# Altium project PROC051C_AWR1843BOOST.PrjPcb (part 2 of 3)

## Sheet PROC051D_QSPI_Flash_Reference.SchDoc: QSPI flash section
size 431 x 279 mm; Date: Not shown in title block; ApprovedBy: Not shown in title block; CheckedBy: Not shown in title block; Author: Not shown in title block; CompanyName: Not shown in title block; Engineer: Not shown in title block; Organization: Not shown in title block; Address1: Not shown in title block; Address2: Not shown in title block; Address3: Not shown in title block; Address4: Not shown in title block; DocumentNumber: 6; Revision: Use project parameter SCH_Rev; SheetNumber: 6; SheetTotal: 16; PageSetup: Record=PageOptions¦CenterHorizontal=True¦CenterVertical=True¦PrintScale=1.00¦XCorrection=1.00¦YCorrection=1.00¦PrintKind=0¦BorderSize=5000000¦LeftOffset=0¦BottomOffset=0¦Orientation=2¦PaperLength=1000¦PaperWidth=1000¦Scale=100¦PaperSource=15¦PrintQuality=600¦MediaType=1¦DitherType=10¦PaperKind=Letter¦PrintScaleMode=1

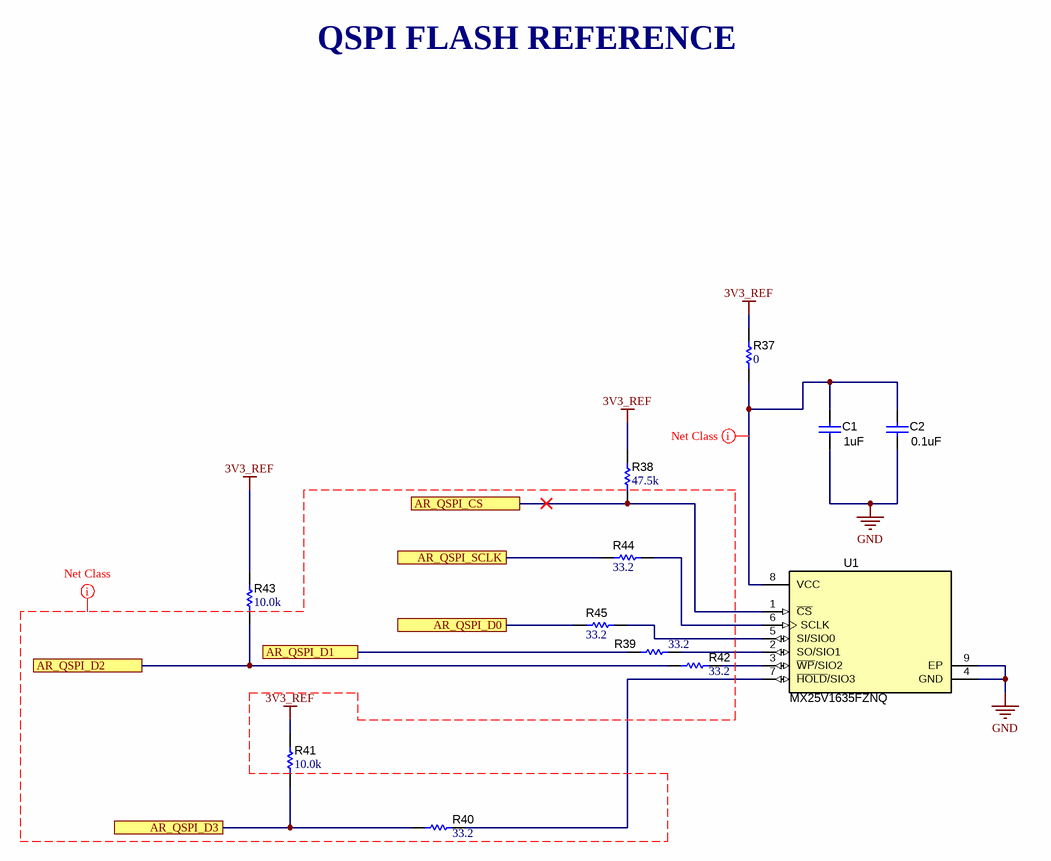
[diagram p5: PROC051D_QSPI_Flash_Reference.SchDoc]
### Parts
C1  ValueDisplayed: 1uF  [0603]  (hidden comment: GCM188R71C105KA64D)
C2  ValueDisplayed: 0.1uF  [0402L]  (hidden comment: CGA2B3X7R1H104K050BB)
R37  ValueDisplayed: 0  [0402L]  (hidden comment: ERJ-2GE0R00X)
R38  ValueDisplayed: 47.5k  [0402L]  (hidden comment: CRCW040247K5FKED)
R39  ValueDisplayed: 33.2  [0201_Silk]  (hidden comment: CRCW020133R2FNED)
R40  ValueDisplayed: 33.2  [0201_Silk]  (hidden comment: CRCW020133R2FNED)
R41  ValueDisplayed: 10.0k  [0402L]  (hidden comment: CRCW040210K0FKED)
R42  ValueDisplayed: 33.2  [0201_Silk]  (hidden comment: CRCW020133R2FNED)
R43  ValueDisplayed: 10.0k  [0402L]  (hidden comment: CRCW040210K0FKED)
R44  ValueDisplayed: 33.2  [0201_Silk]  (hidden comment: CRCW020133R2FNED)
R45  ValueDisplayed: 33.2  [0201_Silk]  (hidden comment: CRCW020133R2FNED)
U1  MX25V1635FZNQ  [WSON-8L_6x5MM_EP]

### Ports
AR_QSPI_CS, AR_QSPI_D0, AR_QSPI_D1, AR_QSPI_D2, AR_QSPI_D3, AR_QSPI_SCLK

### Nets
3V3_REF: R37.1 R38.2 R41.2 R43.2
GND: C1.1 C2.1 U1.4(GND) U1.9(EP)
AR_QSPI_CS: R38.1 U1.1(~{CS}) ; port AR_QSPI_CS
AR_QSPI_D0: R45.2 ; port AR_QSPI_D0
AR_QSPI_D1: R39.1 ; port AR_QSPI_D1
AR_QSPI_D2: R42.1 R43.1 ; port AR_QSPI_D2
AR_QSPI_D3: R40.2 R41.1 ; port AR_QSPI_D3
AR_QSPI_SCLK: R44.2 ; port AR_QSPI_SCLK
NetC1_2: C1.2 C2.2 R37.2 U1.8(VCC)
NetR39_2: R39.2 U1.2(SO/SIO1)
NetR40_1: R40.1 U1.7(~{HOLD}/SIO3)
NetR42_2: R42.2 U1.3(~{WP}/SIO2)
NetR44_1: R44.1 U1.6(SCLK)
NetR45_1: R45.1 U1.5(SI/SIO0)

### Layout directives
net class PWR: NetC1_2
net class QSPI: 3V3_REF

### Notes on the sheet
- QSPI FLASH REFERENCE

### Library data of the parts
C1 = CMP-0007136-5: CAP, CERM, 1 uF, 16 V, +/- 10%, X7R, AEC-Q200 Grade 1, 0603; Manufacturer: MuRata; TaMin_C: -55°C; Polarized: N; SizeAreaWB_mm2: 4.68; Value1: Unknown; U/M: EA; Value: 1uF; TaMax_C: 125°C; SizeZ_mm: 1; SizeX_mm: 1.6; SizeY_mm: 0.8; Value2: 16V; SizeArea_mm2: 1.28; AEC Qualified: Y; Cap_F: 1µF; AEC Category: Q200
C2 = CMP-0006325-2: CAP, CERM, 0.1 uF, 50 V, +/- 10%, X7R, AEC-Q200 Grade 1, 0402; Manufacturer: TDK; TaMin_C: -55°C; ESR_ohm: 0.039064; Polarized: N; SizeAreaWB_mm2: 3; Value1: 0.039064 ohm; U/M: EA; Value: 0.1uF; TaMax_C: 125°C; SizeZ_mm: 0.6; SizeX_mm: 1; SizeY_mm: 0.5; Cap_Case: 0402; Value2: 50V; AEC Qualified: Y; Cap_F: 100nF; IRMS_A: 8.14669dA; AEC Category: Q200
R37 = CMP-0026992-3: RES, 0, 5%, 0.1 W, AEC-Q200 Grade 0, 0402; Manufacturer: Panasonic; Power_W: 100mW; TempCo: 600 ppm/C; Value_Code: 0000; Value: 0; EIA_Code: E24; SizeX_mm: 1; SizeY_mm: 0.5; SizeZ_mm: 0.6; Value2: 0.1W; AEC Qualified: Y; VDC_V: 50V; AEC Category: Q200; SizeAreaWB_mm2: 3
R38 = CMP-0026395-2: RES, 47.5 k, 1%, 0.063 W, AEC-Q200 Grade 0, 0402; Manufacturer: Vishay-Dale; Power_W: 63mW; TempCo: 100 ppm/C; Value_Code: 47k5; Value: 47.5k; EIA_Code: E96; SizeX_mm: 1; SizeY_mm: 0.5; SizeZ_mm: 0.6; Value2: 0.063W; AEC Qualified: Y; VDC_V: 50V; AEC Category: Q200; AEC Grade: 0
R39 R40 R42 R45 = CMP-0027275-3: RES, 33.2, 1%, 0.05 W, 0201; Manufacturer: Vishay-Dale; Power_W: 50mW; TempCo: 200 ppm/C; Value_Code: 33R2; Value: 33.2; EIA_Code: E96; SizeX_mm: 0.6; SizeY_mm: 0.3; SizeZ_mm: 0.26; Value2: 0.05W; SizeArea_mm2: 0.18; AEC Qualified: N; AEC Category: Q200
R41 R43 = CMP-0025958-3: RES, 10.0 k, 1%, 0.063 W, AEC-Q200 Grade 0, 0402; Manufacturer: Vishay-Dale; Power_W: 63mW; TempCo: 100 ppm/C; Value_Code: 10k0; Value: 10.0k; EIA_Code: E96; Res_ohm: 10k; SizeX_mm: 1; SizeY_mm: 0.5; SizeZ_mm: 0.6; Value2: 0.063W; AEC Qualified: Y; VDC_V: 50V; AEC Category: Q200; AEC Grade: 0
R44 = CMP-0027275-3: RES, 33.2, 1%, 0.05 W, 0201; Manufacturer: Vishay-Dale; Power_W: 50mW; TempCo: 200 ppm/C; Value_Code: 33R2; Value: 33.2; EIA_Code: E96; SizeX_mm: 0.6; SizeY_mm: 0.3; SizeZ_mm: 0.26; Value2: 0.05W; SizeArea_mm2: 0.18; CompType: Resistor; AEC Qualified: N; AEC Category: Q200
U1 = CMP-0079267-1: 2.3V-3.6V, 16M-BIT [x 1/x 2/x 4] CMOS FLASH Memory, WSON-8; Manufacturer: Macronix International Co., LTD; SizeArea_mm2: 30; SizeAreaWB_mm2: 56; SizeY_mm: 5; SizeZ_mm: 0.8; SizeX_mm: 6

## Sheet PROC051D_SOP_Headers_Reference.SchDoc
size 431 x 279 mm; Date: Not shown in title block; ApprovedBy: Not shown in title block; CheckedBy: Not shown in title block; Author: Not shown in title block; CompanyName: Not shown in title block; Engineer: Not shown in title block; Organization: Not shown in title block; Address1: Not shown in title block; Address2: Not shown in title block; Address3: Not shown in title block; Address4: Not shown in title block; DocumentNumber: 7; Revision: Use project parameter SCH_Rev; SheetNumber: 7; SheetTotal: 16; PageSetup: Record=PageOptions¦CenterHorizontal=True¦CenterVertical=True¦PrintScale=1.00¦XCorrection=1.00¦YCorrection=1.00¦PrintKind=0¦BorderSize=5000000¦LeftOffset=0¦BottomOffset=0¦Orientation=2¦PaperLength=1000¦PaperWidth=1000¦Scale=100¦PaperSource=15¦PrintQuality=600¦MediaType=1¦DitherType=10¦PaperKind=Letter¦PrintScaleMode=1

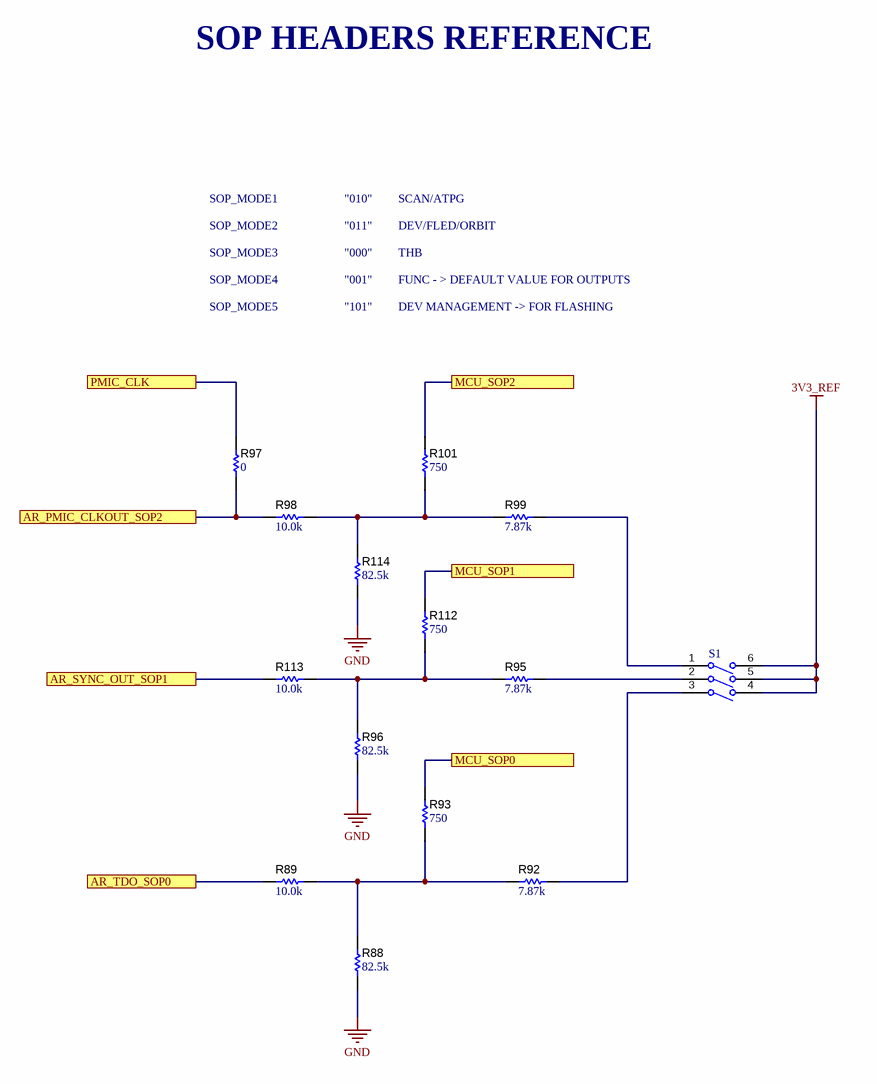
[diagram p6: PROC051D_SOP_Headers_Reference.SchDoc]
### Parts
R88  ValueDisplayed: 82.5k  [0402L]  (hidden comment: CRCW040282K5FKED)
R89  ValueDisplayed: 10.0k  [0402L]  (hidden comment: CRCW040210K0FKED)
R92  ValueDisplayed: 7.87k  [0402L]  (hidden comment: CRCW04027K87FKED)
R93  ValueDisplayed: 750  [0402L]  (hidden comment: CRCW0402750RFKED)
R95  ValueDisplayed: 7.87k  [0402L]  (hidden comment: CRCW04027K87FKED)
R96  ValueDisplayed: 82.5k  [0402L]  (hidden comment: CRCW040282K5FKED)
R97  ValueDisplayed: 0  [0402L]  (hidden comment: ERJ-2GE0R00X)
R98  ValueDisplayed: 10.0k  [0402L]  (hidden comment: CRCW040210K0FKED)
R99  ValueDisplayed: 7.87k  [0402L]  (hidden comment: CRCW04027K87FKED)
R101  ValueDisplayed: 750  [0402L]  (hidden comment: CRCW0402750RFKED)
R112  ValueDisplayed: 750  [0402L]  (hidden comment: CRCW0402750RFKED)
R113  ValueDisplayed: 10.0k  [0402L]  (hidden comment: CRCW040210K0FKED)
R114  ValueDisplayed: 82.5k  [0402L]  (hidden comment: CRCW040282K5FKED)
S1  219-3MST  [SW_219-3MST]  (value not drawn)

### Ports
AR_PMIC_CLKOUT_SOP2, AR_SYNC_OUT_SOP1, AR_TDO_SOP0, MCU_SOP0, MCU_SOP1, MCU_SOP2, PMIC_CLK

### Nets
3V3_REF: S1.4(B3) S1.5(B2) S1.6(B1)
GND: R88.1 R96.1 R114.1
AR_PMIC_CLKOUT_SOP2: R97.1 R98.1 ; port AR_PMIC_CLKOUT_SOP2
AR_SYNC_OUT_SOP1: R113.1 ; port AR_SYNC_OUT_SOP1
AR_TDO_SOP0: R89.1 ; port AR_TDO_SOP0
MCU_SOP0: R93.2 ; port MCU_SOP0
MCU_SOP1: R112.2 ; port MCU_SOP1
MCU_SOP2: R101.2 ; port MCU_SOP2
PMIC_CLK: R97.2 ; port PMIC_CLK
NetR88_2: R88.2 R89.2 R92.1 R93.1
NetR92_2: R92.2 S1.3(A3)
NetR95_1: R95.1 R96.2 R112.1 R113.2
NetR95_2: R95.2 S1.2(A2)
NetR98_2: R98.2 R99.1 R101.1 R114.2
NetR99_2: R99.2 S1.1(A1)

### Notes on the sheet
- SOP HEADERS REFERENCE
- SOP_MODE1
- "010"
- SCAN/ATPG
- SOP_MODE2
- SOP_MODE3
- "011"
- "000"
- DEV/FLED/ORBIT
- THB
- SOP_MODE4
- SOP_MODE5
- "001"
- "101"
- FUNC - > DEFAULT VALUE FOR OUTPUTS
- DEV MANAGEMENT -> FOR FLASHING

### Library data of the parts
R88 R96 R114 = CMP-0026574-2: RES, 82.5 k, 1%, 0.063 W, AEC-Q200 Grade 0, 0402; Manufacturer: Vishay-Dale; Power_W: 63mW; TempCo: 100 ppm/C; Value_Code: 82k5; Value: 82.5k; EIA_Code: E96; SizeX_mm: 1; SizeY_mm: 0.5; SizeZ_mm: 0.6; Value2: 0.063W; AEC Qualified: Y; VDC_V: 50V; AEC Grade: 0; AEC Category: Q200
R89 R98 R113 = CMP-0025958-3: as R41 on sheet PROC051D_QSPI_Flash_Reference
R92 R95 R99 = CMP-0026557-2: RES, 7.87 k, 1%, 0.063 W, AEC-Q200 Grade 0, 0402; Manufacturer: Vishay-Dale; Power_W: 63mW; TempCo: 100 ppm/C; Value_Code: 7k87; Value: 7.87k; EIA_Code: E96; SizeX_mm: 1; SizeY_mm: 0.5; SizeZ_mm: 0.6; Value2: 0.063W; AEC Qualified: Y; VDC_V: 50V; AEC Grade: 0; AEC Category: Q200
R93 R101 R112 = CMP-0026542-2: RES, 750, 1%, 0.063 W, AEC-Q200 Grade 0, 0402; Manufacturer: Vishay-Dale; Power_W: 63mW; TempCo: 100 ppm/C; Value_Code: 750R; Value: 750; EIA_Code: E96; SizeX_mm: 1; SizeY_mm: 0.5; SizeZ_mm: 0.6; Value2: 0.063W; AEC Qualified: Y; VDC_V: 50V; AEC Grade: 0; AEC Category: Q200
R97 = CMP-0026992-3: as R37 on sheet PROC051D_QSPI_Flash_Reference
S1 = CMP-0002269-1: Switch, SPST, Slide, Off-On, 3 Pos, 0.1A, 20V, SMD; Manufacturer: CTS Electrocomponents; CurrentRating_mA: 100A; PositionCount: 3

## Sheet PROC051D_RST_LEDs.SchDoc: Pwr_RST_LEDs
size 431 x 279 mm; Date: Not shown in title block; ApprovedBy: Not shown in title block; CheckedBy: Not shown in title block; Author: Not shown in title block; CompanyName: Not shown in title block; Engineer: Not shown in title block; Organization: Not shown in title block; Address1: Not shown in title block; Address2: Not shown in title block; Address3: Not shown in title block; Address4: Not shown in title block; DocumentNumber: 8; Revision: Use project parameter SCH_Rev; SheetNumber: 8; SheetTotal: 16; PageSetup: Record=PageOptions¦CenterHorizontal=True¦CenterVertical=True¦PrintScale=1.00¦XCorrection=1.00¦YCorrection=1.00¦PrintKind=0¦BorderSize=5000000¦LeftOffset=0¦BottomOffset=0¦Orientation=2¦PaperLength=1000¦PaperWidth=1000¦Scale=100¦PaperSource=15¦PrintQuality=600¦MediaType=1¦DitherType=10¦PaperKind=Letter¦PrintScaleMode=1

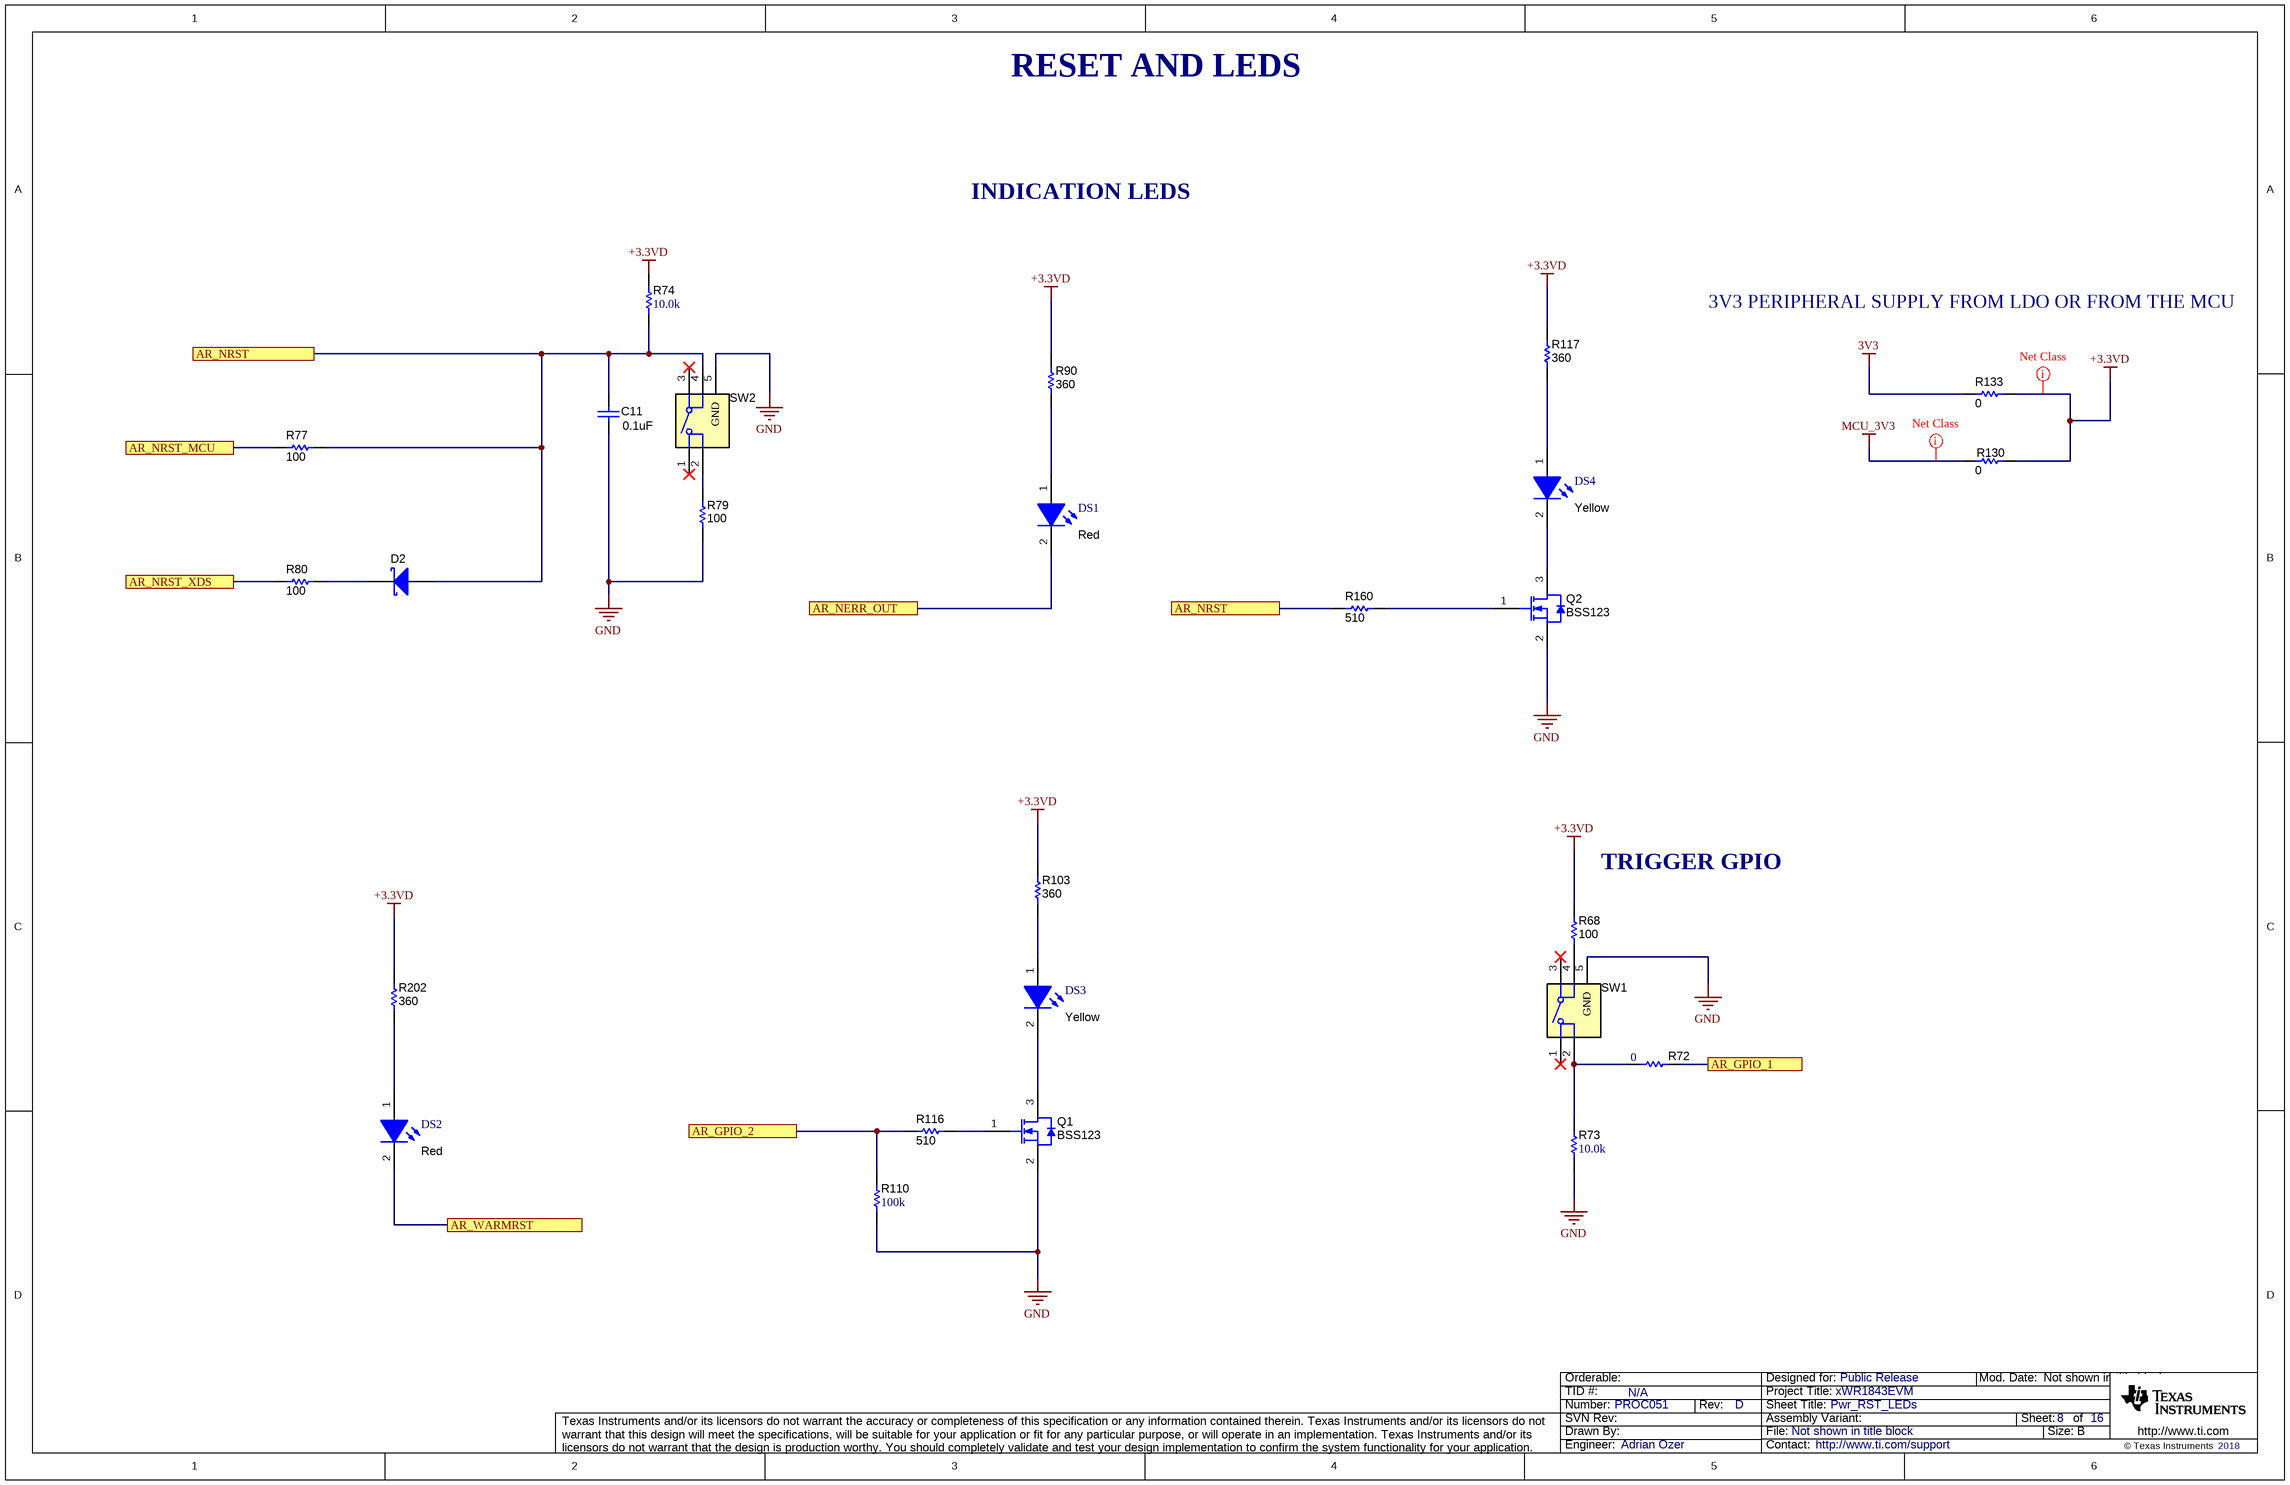
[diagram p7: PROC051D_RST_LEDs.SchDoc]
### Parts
C11  ValueDisplayed: 0.1uF  [0402L]  (hidden comment: GCM155R71C104KA55D)
D2  SMS3923-040LF  [SOD-882]  (value not drawn)
DS1  value Red  [LS L29K_Red]  (hidden comment: LS L29K-G1J2-1-Z)
DS2  value Red  [LS L29K_Red]  (hidden comment: LS L29K-G1J2-1-Z)
DS3  value Yellow  [SML-E1_Yellow]  (hidden comment: SML-E12Y8WT86)
DS4  value Yellow  [SML-E1_Yellow]  (hidden comment: SML-E12Y8WT86)
Q1  BSS123  [SOT-23]
Q2  BSS123  [SOT-23]
R68  ValueDisplayed: 100  [0402L]  (hidden comment: ERJ-2GEJ101X)
R72  ValueDisplayed: 0  [0201_Silk]  (hidden comment: CRCW02010000Z0ED)
R73  ValueDisplayed: 10.0k  [0402L]  (hidden comment: CRCW040210K0FKED)
R74  ValueDisplayed: 10.0k  [0402L]  (hidden comment: CRCW040210K0FKED)
R77  ValueDisplayed: 100  [0402L]  (hidden comment: ERJ-2GEJ101X)
R79  ValueDisplayed: 100  [0402L]  (hidden comment: ERJ-2GEJ101X)
R80  ValueDisplayed: 100  [0402L]  (hidden comment: ERJ-2GEJ101X)
R90  ValueDisplayed: 360  [0402L]  (hidden comment: ERJ-2GEJ361X)
R103  ValueDisplayed: 360  [0402L]  (hidden comment: ERJ-2GEJ361X)
R110  ValueDisplayed: 100k  [0402L]  (hidden comment: CRCW0402100KFKED)
R116  ValueDisplayed: 510  [0402L]  (hidden comment: ERJ-2GEJ511X)
R117  ValueDisplayed: 360  [0402L]  (hidden comment: ERJ-2GEJ361X)
R130  ValueDisplayed: 0  [0603]  (hidden comment: MCT06030Z0000ZP500)
R133  ValueDisplayed: 0  [0603]  (hidden comment: MCT06030Z0000ZP500)
R160  ValueDisplayed: 510  [0402L]  (hidden comment: ERJ-2GEJ511X)
R202  ValueDisplayed: 360  [0402L]  (hidden comment: ERJ-2GEJ361X)
SW1  KMR243GLFG  [SW_KMR243GLFG]  (value not drawn)
SW2  KMR243GLFG  [SW_KMR243GLFG]  (value not drawn)

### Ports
AR_GPIO_1, AR_GPIO_2, AR_NERR_OUT, AR_NRST, AR_NRST_MCU, AR_NRST_XDS, AR_WARMRST

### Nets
3V3: R133.1
+3.3VD: R68.2 R74.2 R90.2 R103.2 R117.2 R130.2 R133.2 R202.2
GND: C11.1 Q1.2(S) Q2.2(S) R73.1 R79.1 R110.1 SW1.5(GND) SW2.5(GND)
MCU_3V3: R130.1
AR_GPIO_1: R72.2 ; port AR_GPIO_1
AR_GPIO_2: R110.2 R116.1 ; port AR_GPIO_2
AR_NERR_OUT: DS1.2(K) ; port AR_NERR_OUT
AR_NRST: C11.2 D2.2(A) R74.1 R77.2 R160.1 SW2.4 ; port AR_NRST
AR_NRST_MCU: R77.1 ; port AR_NRST_MCU
AR_NRST_XDS: R80.1 ; port AR_NRST_XDS
AR_WARMRST: DS2.2(K) ; port AR_WARMRST
NetD2_1: D2.1(K) R80.2
NetDS1_1: DS1.1(A) R90.1
NetDS2_1: DS2.1(A) R202.1
NetDS3_1: DS3.1(A) R103.1
NetDS3_2: DS3.2(K) Q1.3(D)
NetDS4_1: DS4.1(A) R117.1
NetDS4_2: DS4.2(K) Q2.3(D)
NetQ1_1: Q1.1(G) R116.2
NetQ2_1: Q2.1(G) R160.2
NetR68_1: R68.1 SW1.4
NetR72_1: R72.1 R73.2 SW1.2
NetR79_2: R79.2 SW2.2

Not connected (* = marked no-connect by the designer): SW1 1* 3*; SW2 1* 3*

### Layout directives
net class PWR: +3.3VD, MCU_3V3

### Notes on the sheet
- RESET AND LEDS
- INDICATION LEDS
- 3V3 PERIPHERAL SUPPLY FROM LDO OR FROM THE MCU
- (near R68) TRIGGER GPIO

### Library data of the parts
C11 = CMP-0006351-2: CAP, CERM, 0.1 uF, 16 V, +/- 10%, X7R, 0402; Manufacturer: MuRata; TaMin_C: -55°C; Polarized: N; SizeAreaWB_mm2: 3; Value1: Unknown; U/M: EA; Value: 0.1uF; TaMax_C: 125°C; SizeZ_mm: 0.6; SizeX_mm: 1; SizeY_mm: 0.5; Cap_Case: 0402; Value2: 16V; Cap_F: 100nF; AEC Category: Q200
D2 = CMP-0078187-2: Diode, Schottky,  V, 0.01 A, SOD-882; Manufacturer: Skyworks Solutions; SizeAreaWB_mm2: 3.2; SizeArea_mm2: 0.6; AEC Qualified: N; TJmax_C: 150°C; AEC Category: Q101; SizeZ_mm: 0.5; Io_A: 10mA; Vf_V: 340mV; Value2: 0.34V; Value1: 0.01A; SizeX_mm: 1
DS1 DS2 = CMP-0002902-2: LED, Red, SMD; Manufacturer: OSRAM; Io_A: 20mA; Vr_V: 12V; Tjmax_C: 110°C; Value1: W; Angle: 160; Vf_V: 1.8V
DS3 DS4 = CMP-0002977-3: LED, Yellow, SMD; Manufacturer: Rohm; Io_A: 20mA; Power_TotalModule: 54mW; Vr_V: 5V; Tjmax_C: 85°C; Value1: 0.054W; Ir_A: 10µA; Vf_V: 2.2V; LuminousIntensity_IV: 63
Q1 Q2 = CMP-0000947-2: MOSFET, N-CH, 100 V, 0.17 A, SOT-23; Alternate Manufacturer: None; Manufacturer: Fairchild Semiconductor; SizeZ_mm: 1.1; ChType: N; Value2: 1.8 nC; Value1: 1; VdsMax_V: 100V; SizeX_mm: 2.5; SizeY_mm: 3; Vgs_V: 20V; Value: 100V; Rdson45_ohm: 10; SizeArea_mm2: 7.5; AEC Category: Q101; IdsMax_A: 1.7dA; SizeAreaWB_mm2: 14; U/M: EA; QgTyp_nC: 1.8
R68 R77 R79 R80 = CMP-0026993-2: RES, 100, 5%, 0.1 W, AEC-Q200 Grade 0, 0402; Manufacturer: Panasonic; Power_W: 100mW; TempCo: 200 ppm/C; Value_Code: 100R; U/M: EA; Value: 100; EIA_Code: E24; SizeX_mm: 1; SizeY_mm: 0.5; SizeZ_mm: 0.6; Value2: 0.1W; AEC Qualified: Y; AEC Grade: 0; AEC Category: Q200
R72 = CMP-0027008-4: RES, 0, 5%, 0.05 W, 0201; Manufacturer: Vishay-Dale; Power_W: 50mW; TempCo: ppm/C; Value_Code: 0000; Value: 0; EIA_Code: E24; SizeX_mm: 0.6; SizeY_mm: 0.3; SizeZ_mm: 0.26; Value2: 0.05W; SizeArea_mm2: 0.18; AEC Qualified: N; AEC Category: Q200
R73 R74 = CMP-0025958-3: as R41 on sheet PROC051D_QSPI_Flash_Reference
R90 R103 R117 R202 = CMP-0078194-1: RES, 360, 5%, 0.1 W, AEC-Q200 Grade 0, 0402; Manufacturer: Panasonic; Value_Code: 360R; SizeArea_mm2: 0.5; AEC Qualified: Y; AEC Category: Q200; Value: 360; SizeZ_mm: 0.6; EIA_Code: E24; TempCo: 200 ppm/C; AEC Grade: 0; Power_W: 100mW; VDC_V: 50V; Value2: 0.1W; U/M: EA; SizeX_mm: 1
R110 = CMP-0025950-3: RES, 100 k, 1%, 0.063 W, AEC-Q200 Grade 0, 0402; Manufacturer: Vishay-Dale; Power_W: 63mW; TempCo: 100 ppm/C; Value: 100k; EIA_Code: E96; SizeX_mm: 1; SizeY_mm: 0.5; SizeZ_mm: 0.6; Value2: 0.063W; AEC Qualified: Y; VDC_V: 50V; AEC Category: Q200; AEC Grade: 0
R116 R160 = CMP-0078212-1: RES, 510, 5%, 0.1 W, AEC-Q200 Grade 0, 0402; Manufacturer: Panasonic; Value_Code: 510R; SizeArea_mm2: 0.5; AEC Qualified: Y; AEC Category: Q200; Value: 510; SizeZ_mm: 0.6; EIA_Code: E24; TempCo: 200 ppm/C; AEC Grade: 0; Power_W: 100mW; VDC_V: 50V; Value2: 0.1W; U/M: EA; SizeX_mm: 1
R130 = CMP-0025884-3: RES, 0, 5%, 0.125 W, 0603; Manufacturer: Vishay/Beyschlag; Power_W: 125mW; TempCo: ppm/C; Value_Code: 0000; U/M: EA; Value: 0; EIA_Code: E24; SizeX_mm: 1.6; SizeY_mm: 0.8; SizeZ_mm: 1; Value2: 0.125W; SizeArea_mm2: 1.28; CompType: Resistor; AEC Qualified: N; AEC Category: Q200
R133 = CMP-0025884-3: RES, 0, 5%, 0.125 W, 0603; Manufacturer: Vishay/Beyschlag; Power_W: 125mW; TempCo: ppm/C; Value_Code: 0000; U/M: EA; Value: 0; EIA_Code: E24; SizeX_mm: 1.6; SizeY_mm: 0.8; SizeZ_mm: 1; Value2: 0.125W; SizeArea_mm2: 1.28; AEC Qualified: N; AEC Category: Q200
SW1 SW2 = CMP-0002325-1: Switch, SPST-NO, Off-Mom, 0.01 A, 32 VDC, SMD; Manufacturer: C&K Components; CurrentRating_mA: 10A; PositionCount: 1; SizeX_mm: 4.6; SizeY_mm: 2.8; SizeZ_mm: 1.9; SizeArea_mm2: 12.88; VDC_V: 32V; SizeAreaWB_mm2: 21.28

## Sheet PROC051D_VPP_Supply.SchDoc: VPP_Supply
size 431 x 279 mm; Date: Not shown in title block; ApprovedBy: Not shown in title block; CheckedBy: Not shown in title block; Author: Not shown in title block; CompanyName: Not shown in title block; Engineer: Not shown in title block; Organization: Not shown in title block; Address1: Not shown in title block; Address2: Not shown in title block; Address3: Not shown in title block; Address4: Not shown in title block; DocumentNumber: 9; Revision: Use project parameter SCH_Rev; SheetNumber: 9; SheetTotal: 16; PageSetup: Record=PageOptions¦CenterHorizontal=True¦CenterVertical=True¦PrintScale=1.00¦XCorrection=1.00¦YCorrection=1.00¦PrintKind=0¦BorderSize=5000000¦LeftOffset=0¦BottomOffset=0¦Orientation=2¦PaperLength=1000¦PaperWidth=1000¦Scale=100¦PaperSource=15¦PrintQuality=600¦MediaType=1¦DitherType=10¦PaperKind=Letter¦PrintScaleMode=1

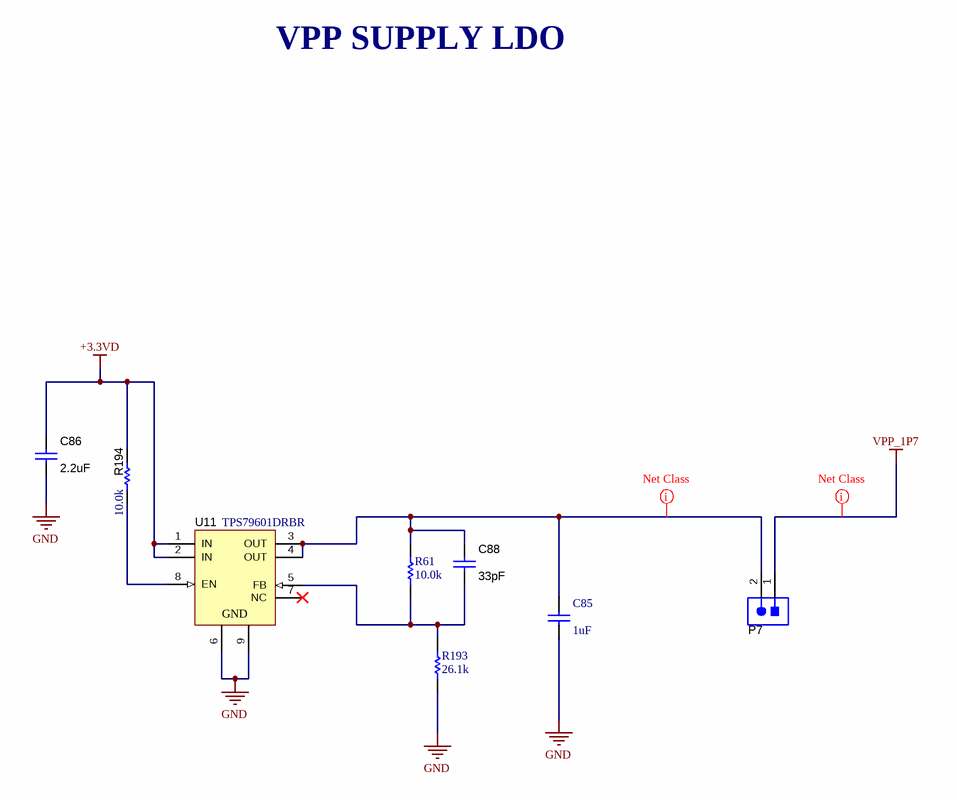
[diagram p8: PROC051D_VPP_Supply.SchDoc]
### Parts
C85  ValueDisplayed: 1uF  [0402]  (hidden comment: GRM155R70J105MA12D)
C86  ValueDisplayed: 2.2uF  [0402_065L]  (hidden comment: C1005X7S1A225K050BC)
C88  ValueDisplayed: 33pF  [0402L]  (hidden comment: C0402C330J5GAC)
P7  TSW-102-07-G-S  [TSW-102-07-G-S]  (value not drawn)
R61  ValueDisplayed: 10.0k  [0402]  (hidden comment: ERJ-2RKF1002X)
R193  ValueDisplayed: 26.1k  [0402]  (hidden comment: CRCW040226K1FKED)
R194  ValueDisplayed: 10.0k  [0402L]  (hidden comment: CRCW040210K0FKED)
U11  TPS79601DRBR  [DRB0008B]

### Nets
+3.3VD: C86.2 R194.1 U11.1(IN) U11.2(IN)
GND: C85.2 C86.1 R193.1 U11.6(GND) U11.9(GND)
VPP_1P7: P7.1
NetC85_1: C85.1 C88.1 P7.2 R61.2 U11.3(OUT) U11.4(OUT)
NetC88_2: C88.2 R61.1 R193.2 U11.5(FB)
NetR194_2: R194.2 U11.8(EN)

Not connected (* = marked no-connect by the designer): U11 7(NC)*

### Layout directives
net class PWR: NetC85_1, VPP_1P7

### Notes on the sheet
- VPP SUPPLY LDO

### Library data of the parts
C85 = CMP-0006624-2: CAP, CERM, 1 uF, 6.3 V, +/- 20%, X7R, 0402; Manufacturer: MuRata; TaMin_C: -55°C; Polarized: N; SizeAreaWB_mm2: 3; Value1: Unknown; U/M: EA; Value: 1uF; TaMax_C: 125°C; SizeZ_mm: 0.6; SizeX_mm: 1; SizeY_mm: 0.5; Value2: 6.3V; Cap_F: 1µF; AEC Category: Q200
C86 = CMP-0006302-2: CAP, CERM, 2.2 uF, 10 V, +/- 10%, X7S, 0402; Manufacturer: TDK; TaMin_C: -55°C; ESR_ohm: 5.925m; Polarized: N; SizeAreaWB_mm2: 3; Value1: 0.005925 ohm; U/M: EA; Value: 2.2uF; TaMax_C: 125°C; SizeZ_mm: 0.65; SizeX_mm: 1; SizeY_mm: 0.5; Cap_Case: 0402_065; Value2: 10V; CompType: Capacitor; Cap_F: 2.2µF; IRMS_A: 2.05591A; AEC Category: Q200
C88 = CMP-0006242-2: CAP, CERM, 33 pF, 50 V, +/- 5%, C0G/NP0, 0402; Manufacturer: Kemet; TaMin_C: -55°C; Polarized: N; SizeAreaWB_mm2: 3; Value1: Unknown; U/M: EA; Value: 33pF; TaMax_C: 125°C; SizeZ_mm: 0.6; SizeX_mm: 1; SizeY_mm: 0.5; Cap_Case: 0402; Value2: 50V; AEC Category: Q200
P7 = CMP-0075405-2: Header, 100mil, 2x1, Gold, TH; Manufacturer: Samtec; Pitch_mm: 2.54; Cert_VDE: N; Gender: Male; Cert_CSA: Y; Voltage_V: 550V; Green_REACh: Passed; Current_A: 6.3A; Green_Lifecycle: Active; Row_Count: 1
R61 = CMP-0026658-1: RES, 10.0 k, 1%, 0.1 W, 0402; Manufacturer: Panasonic; Power_W: 100mW; TempCo: 100 ppm/C; Value_Code: 10k0; U/M: EA; Value: 10.0k; EIA_Code: E96; Res_ohm: 10k; SizeX_mm: 1; SizeY_mm: 0.5; SizeZ_mm: 0.6; Value2: 0.1W; VDC_V: 50V; AEC Category: Q200
R193 = CMP-0026207-2: RES, 26.1 k, 1%, 0.063 W, AEC-Q200 Grade 0, 0402; Manufacturer: Vishay-Dale; Power_W: 63mW; TempCo: 100 ppm/C; Value_Code: 26k1; Value: 26.1k; EIA_Code: E96; SizeX_mm: 1; SizeY_mm: 0.5; SizeZ_mm: 0.6; Value2: 0.063W; AEC Qualified: Y; VDC_V: 50V; AEC Category: Q200; AEC Grade: 0
R194 = CMP-0025958-3: as R41 on sheet PROC051D_QSPI_Flash_Reference
U11 = CMP-0036402-3: Single Output High PSRR LDO, 1 A, Adjustable 1.2 to 5.5 V Output, 2.7 to 5.5 V Input, 8-pin SON (DRB), -40 to 125 degC, Green (RoHS & no Sb/Br); Manufacturer: Texas Instruments; Vin(Min)(V): 2.7; Vout Adj(Max)(V): 5.5; Vout Adj(Min)(V): 1.2; Accuracy(%): 2; SubFamily: Single Channel LDO; Iq(Typ)(mA): 0.26; Vdo(Typ)(mV): 250; Iout(Max)(A): 1; AEC Category: Q200; AEC Qualified: N; CompType: IC; SizeArea_mm2: 9.0; SizeAreaWB_mm2: 16.0; SizeX_mm: 3.0; SizeZ_mm: 1.0

## Sheet PROC051D_HD Connector.SchDoc: HD Connector
size 431 x 279 mm; Date: Not shown in title block; ApprovedBy: Not shown in title block; CheckedBy: Not shown in title block; Author: Not shown in title block; CompanyName: Not shown in title block; Engineer: Not shown in title block; Organization: Not shown in title block; Address1: Not shown in title block; Address2: Not shown in title block; Address3: Not shown in title block; Address4: Not shown in title block; DocumentNumber: 10; Revision: Use project parameter SCH_Rev; SheetNumber: 10; SheetTotal: 16; PageSetup: Record=PageOptions¦CenterHorizontal=True¦CenterVertical=True¦PrintScale=1.00¦XCorrection=1.00¦YCorrection=1.00¦PrintKind=0¦BorderSize=5000000¦LeftOffset=0¦BottomOffset=0¦Orientation=2¦PaperLength=1000¦PaperWidth=1000¦Scale=100¦PaperSource=15¦PrintQuality=600¦MediaType=1¦DitherType=10¦PrintScaleMode=1¦PaperKind=Letter

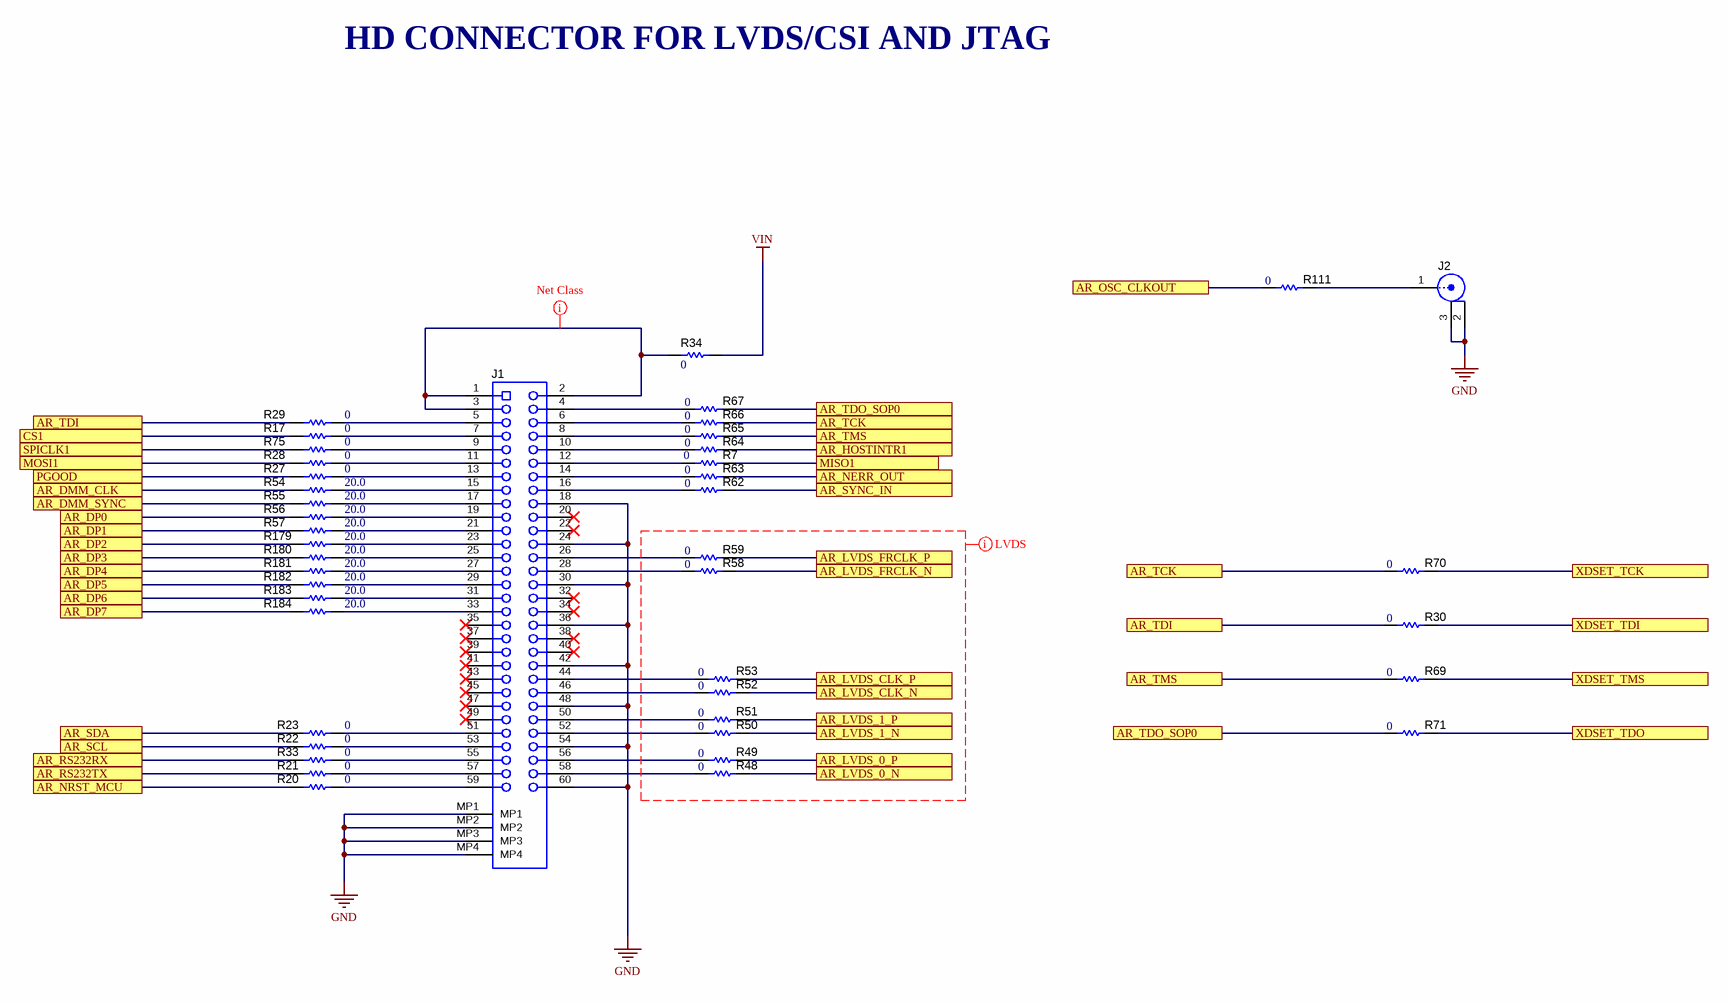
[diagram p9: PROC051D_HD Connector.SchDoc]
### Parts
J1  QSH-030-01-L-D-A  [Samtec_QSH-030-01-X-D-A]  (value not drawn)
J2  128-0711-201  [Johnson_128-0711-201]  (value not drawn)
R7  ValueDisplayed: 0  [0201_Silk]  (hidden comment: CRCW02010000Z0ED)
R17  ValueDisplayed: 0  [0201_Silk]  (hidden comment: CRCW02010000Z0ED)
R20  ValueDisplayed: 0  [0201_Silk]  (hidden comment: CRCW02010000Z0ED)
R21  ValueDisplayed: 0  [0201_Silk]  (hidden comment: CRCW02010000Z0ED)
R22  ValueDisplayed: 0  [0201_Silk]  (hidden comment: CRCW02010000Z0ED)
R23  ValueDisplayed: 0  [0201_Silk]  (hidden comment: CRCW02010000Z0ED)
R27  ValueDisplayed: 0  [0201_Silk]  (hidden comment: CRCW02010000Z0ED)
R28  ValueDisplayed: 0  [0201_Silk]  (hidden comment: CRCW02010000Z0ED)
R29  ValueDisplayed: 0  [0201_Silk]  (hidden comment: CRCW02010000Z0ED)
R30  ValueDisplayed: 0  [0201_Silk]  (hidden comment: CRCW02010000Z0ED)
R33  ValueDisplayed: 0  [0201_Silk]  (hidden comment: CRCW02010000Z0ED)
R34  ValueDisplayed: 0  [2010]  (hidden comment: CRCW20100000Z0EF)
R48  ValueDisplayed: 0  [0201_Silk]  (hidden comment: CRCW02010000Z0ED)
R49  ValueDisplayed: 0  [0201_Silk]  (hidden comment: CRCW02010000Z0ED)
R50  ValueDisplayed: 0  [0201_Silk]  (hidden comment: CRCW02010000Z0ED)
R51  ValueDisplayed: 0  [0201_Silk]  (hidden comment: CRCW02010000Z0ED)
R52  ValueDisplayed: 0  [0201_Silk]  (hidden comment: CRCW02010000Z0ED)
R53  ValueDisplayed: 0  [0201_Silk]  (hidden comment: CRCW02010000Z0ED)
R54  ValueDisplayed: 20.0  [0201_033]  (hidden comment: CRCW020120R0FNED)
R55  ValueDisplayed: 20.0  [0201_033]  (hidden comment: CRCW020120R0FNED)
R56  ValueDisplayed: 20.0  [0201_033]  (hidden comment: CRCW020120R0FNED)
R57  ValueDisplayed: 20.0  [0201_033]  (hidden comment: CRCW020120R0FNED)
R58  ValueDisplayed: 0  [0201_Silk]  (hidden comment: CRCW02010000Z0ED)
R59  ValueDisplayed: 0  [0201_Silk]  (hidden comment: CRCW02010000Z0ED)
R62  ValueDisplayed: 0  [0201_Silk]  (hidden comment: CRCW02010000Z0ED)
R63  ValueDisplayed: 0  [0201_Silk]  (hidden comment: CRCW02010000Z0ED)
R64  ValueDisplayed: 0  [0201_Silk]  (hidden comment: CRCW02010000Z0ED)
R65  ValueDisplayed: 0  [0201_Silk]  (hidden comment: CRCW02010000Z0ED)
R66  ValueDisplayed: 0  [0201_Silk]  (hidden comment: CRCW02010000Z0ED)
R67  ValueDisplayed: 0  [0201_Silk]  (hidden comment: CRCW02010000Z0ED)
R69  ValueDisplayed: 0  [0201_Silk]  (hidden comment: CRCW02010000Z0ED)
R70  ValueDisplayed: 0  [0201_Silk]  (hidden comment: CRCW02010000Z0ED)
R71  ValueDisplayed: 0  [0201_Silk]  (hidden comment: CRCW02010000Z0ED)
R75  ValueDisplayed: 0  [0201_Silk]  (hidden comment: CRCW02010000Z0ED)
R111  ValueDisplayed: 0  [0201_Silk]  (hidden comment: CRCW02010000Z0ED)
R179  ValueDisplayed: 20.0  [0201_033]  (hidden comment: CRCW020120R0FNED)
R180  ValueDisplayed: 20.0  [0201_033]  (hidden comment: CRCW020120R0FNED)
R181  ValueDisplayed: 20.0  [0201_033]  (hidden comment: CRCW020120R0FNED)
R182  ValueDisplayed: 20.0  [0201_033]  (hidden comment: CRCW020120R0FNED)
R183  ValueDisplayed: 20.0  [0201_033]  (hidden comment: CRCW020120R0FNED)
R184  ValueDisplayed: 20.0  [0201_033]  (hidden comment: CRCW020120R0FNED)

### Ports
AR_DMM_CLK, AR_DMM_SYNC, AR_DP0, AR_DP1, AR_DP2, AR_DP3, AR_DP4, AR_DP5, AR_DP6, AR_DP7, AR_HOSTINTR1, AR_LVDS_0_N, AR_LVDS_0_P, AR_LVDS_1_N, AR_LVDS_1_P, AR_LVDS_CLK_N, AR_LVDS_CLK_P, AR_LVDS_FRCLK_N, AR_LVDS_FRCLK_P, AR_NERR_OUT, AR_NRST_MCU, AR_OSC_CLKOUT, AR_RS232RX, AR_RS232TX, AR_SCL, AR_SDA, AR_SYNC_IN, AR_TCK, AR_TDI, AR_TDO_SOP0, AR_TMS, CS1, MISO1, MOSI1, PGOOD, SPICLK1, XDSET_TCK, XDSET_TDI, XDSET_TDO, XDSET_TMS

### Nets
GND: J1.18 J1.24 J1.30 J1.36 J1.42 J1.48 J1.54 J1.60 J1.MP1 J1.MP2 J1.MP3 J1.MP4 J2.2 J2.3
VIN: R34.2
AR_DMM_CLK: R54.1 ; port AR_DMM_CLK
AR_DMM_SYNC: R55.1 ; port AR_DMM_SYNC
AR_DP0: R56.1 ; port AR_DP0
AR_DP1: R57.1 ; port AR_DP1
AR_DP2: R179.1 ; port AR_DP2
AR_DP3: R180.1 ; port AR_DP3
AR_DP4: R181.1 ; port AR_DP4
AR_DP5: R182.1 ; port AR_DP5
AR_DP6: R183.1 ; port AR_DP6
AR_DP7: R184.1 ; port AR_DP7
AR_HOSTINTR1: R64.2 ; port AR_HOSTINTR1
AR_LVDS_0_N: R48.2 ; port AR_LVDS_0_N
AR_LVDS_0_P: R49.2 ; port AR_LVDS_0_P
AR_LVDS_1_N: R50.2 ; port AR_LVDS_1_N
AR_LVDS_1_P: R51.2 ; port AR_LVDS_1_P
AR_LVDS_CLK_N: R52.2 ; port AR_LVDS_CLK_N
AR_LVDS_CLK_P: R53.2 ; port AR_LVDS_CLK_P
AR_LVDS_FRCLK_N: R58.2 ; port AR_LVDS_FRCLK_N
AR_LVDS_FRCLK_P: R59.2 ; port AR_LVDS_FRCLK_P
AR_NERR_OUT: R63.2 ; port AR_NERR_OUT
AR_NRST_MCU: R20.1 ; port AR_NRST_MCU
AR_OSC_CLKOUT: R111.1 ; port AR_OSC_CLKOUT
AR_RS232RX: R33.1 ; port AR_RS232RX
AR_RS232TX: R21.1 ; port AR_RS232TX
AR_SCL: R22.1 ; port AR_SCL
AR_SDA: R23.1 ; port AR_SDA
AR_SYNC_IN: R62.2 ; port AR_SYNC_IN
AR_TCK: R66.2 R70.1 ; port AR_TCK
AR_TDI: R29.1 R30.1 ; port AR_TDI
AR_TDO_SOP0: R67.2 R71.1 ; port AR_TDO_SOP0
AR_TMS: R65.2 R69.1 ; port AR_TMS
CS1: R17.1 ; port CS1
MISO1: R7.2 ; port MISO1
MOSI1: R28.1 ; port MOSI1
PGOOD: R27.1 ; port PGOOD
SPICLK1: R75.1 ; port SPICLK1
XDSET_TCK: R70.2 ; port XDSET_TCK
XDSET_TDI: R30.2 ; port XDSET_TDI
XDSET_TDO: R71.2 ; port XDSET_TDO
XDSET_TMS: R69.2 ; port XDSET_TMS
NetJ1_1: J1.1 J1.2 J1.3 R34.1
NetJ1_4: J1.4 R67.1
NetJ1_5: J1.5 R29.2
NetJ1_6: J1.6 R66.1
NetJ1_7: J1.7 R17.2
NetJ1_8: J1.8 R65.1
NetJ1_9: J1.9 R75.2
NetJ1_10: J1.10 R64.1
NetJ1_11: J1.11 R28.2
NetJ1_12: J1.12 R7.1
NetJ1_13: J1.13 R27.2
NetJ1_14: J1.14 R63.1
NetJ1_15: J1.15 R54.2
NetJ1_16: J1.16 R62.1
NetJ1_17: J1.17 R55.2
NetJ1_19: J1.19 R56.2
NetJ1_21: J1.21 R57.2
NetJ1_23: J1.23 R179.2
NetJ1_25: J1.25 R180.2
NetJ1_26: J1.26 R59.1
NetJ1_27: J1.27 R181.2
NetJ1_28: J1.28 R58.1
NetJ1_29: J1.29 R182.2
NetJ1_31: J1.31 R183.2
NetJ1_33: J1.33 R184.2
NetJ1_44: J1.44 R53.1
NetJ1_46: J1.46 R52.1
NetJ1_50: J1.50 R51.1
NetJ1_51: J1.51 R23.2
NetJ1_52: J1.52 R50.1
NetJ1_53: J1.53 R22.2
NetJ1_55: J1.55 R33.2
NetJ1_56: J1.56 R49.1
NetJ1_57: J1.57 R21.2
NetJ1_58: J1.58 R48.1
NetJ1_59: J1.59 R20.2
NetJ2_1: J2.1 R111.2

Not connected (* = marked no-connect by the designer): J1 20* 22* 32* 34* 35* 37* 38* 39* 40* 41* 43* 45* 47* 49*

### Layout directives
net class Undefined: (no net found under the mark)
net class PWR: NetJ1_1

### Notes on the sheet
- HD CONNECTOR FOR LVDS/CSI AND JTAG

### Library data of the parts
J1 = CMP-0075524-1: Receptacle, 0.5 mm, 30x2, Gold, TH; Manufacturer: Samtec; Pitch_mm: 0.5; Gender: Female; Green_REACh: Passed; CT: False; Shrouded: N; RowSpacing_mm: 5.73; Green_Lifecycle: Active; Row_Count: 2
J2 = CMP-0055788-1: UMC Straight Jack Receptacle, 50 Ohm, Gold, SMT; Manufacturer: Cinch Connectivity; CNHeader: FALSE; Gender: Female
R7 R17 R20-R23 R27-R30 R33 R48-R53 R58 R59 R62-R67 R69-R71 R75 R111 = CMP-0027008-4: as R72 on sheet PROC051D_RST_LEDs
R34 = CMP-0016044-3: RES, 0, 5%, 0.75 W, AEC-Q200 Grade 0, 2010; Manufacturer: Vishay-Dale; Power_W: 750mW; TempCo: ppm/C; Value_Code: 0000; Value: 0; EIA_Code: E24; SizeX_mm: 5; SizeY_mm: 2.5; SizeZ_mm: 1.66; Value2: 0.75W; SizeArea_mm2: 12.5; AEC Qualified: Y; AEC Category: Q200
R54-R57 R179-R184 = CMP-0078192-2: RES, 20.0, 1%, 0.05 W, 0201; Manufacturer: Vishay-Dale; Value_Code: 20R0; SizeArea_mm2: 0.18; AEC Qualified: N; AEC Category: Q200; Res_ohm: 20; Value: 20.0; SizeZ_mm: 0.33; EIA_Code: E96; TempCo: 200 ppm/C; Power_W: 50mW; VDC_V: 30V; SizeY_mm: 0.3; Value2: 0.05W; SizeX_mm: 0.6

## Sheet PROC051D_LP Connector.SchDoc: LP Connector
size 431 x 279 mm; Date: Not shown in title block; ApprovedBy: Not shown in title block; CheckedBy: Not shown in title block; Author: Not shown in title block; CompanyName: Not shown in title block; Engineer: Not shown in title block; Organization: Not shown in title block; Address1: Not shown in title block; Address2: Not shown in title block; Address3: Not shown in title block; Address4: Not shown in title block; DocumentNumber: 11; Revision: Use project parameter SCH_Rev; SheetNumber: 11; SheetTotal: 16; PageSetup: Record=PageOptions¦CenterHorizontal=True¦CenterVertical=True¦PrintScale=1.00¦XCorrection=1.00¦YCorrection=1.00¦PrintKind=0¦BorderSize=5000000¦LeftOffset=0¦BottomOffset=0¦Orientation=2¦PaperLength=1000¦PaperWidth=1000¦Scale=100¦PaperSource=15¦PrintQuality=600¦MediaType=1¦DitherType=10¦PaperKind=Letter¦PrintScaleMode=1

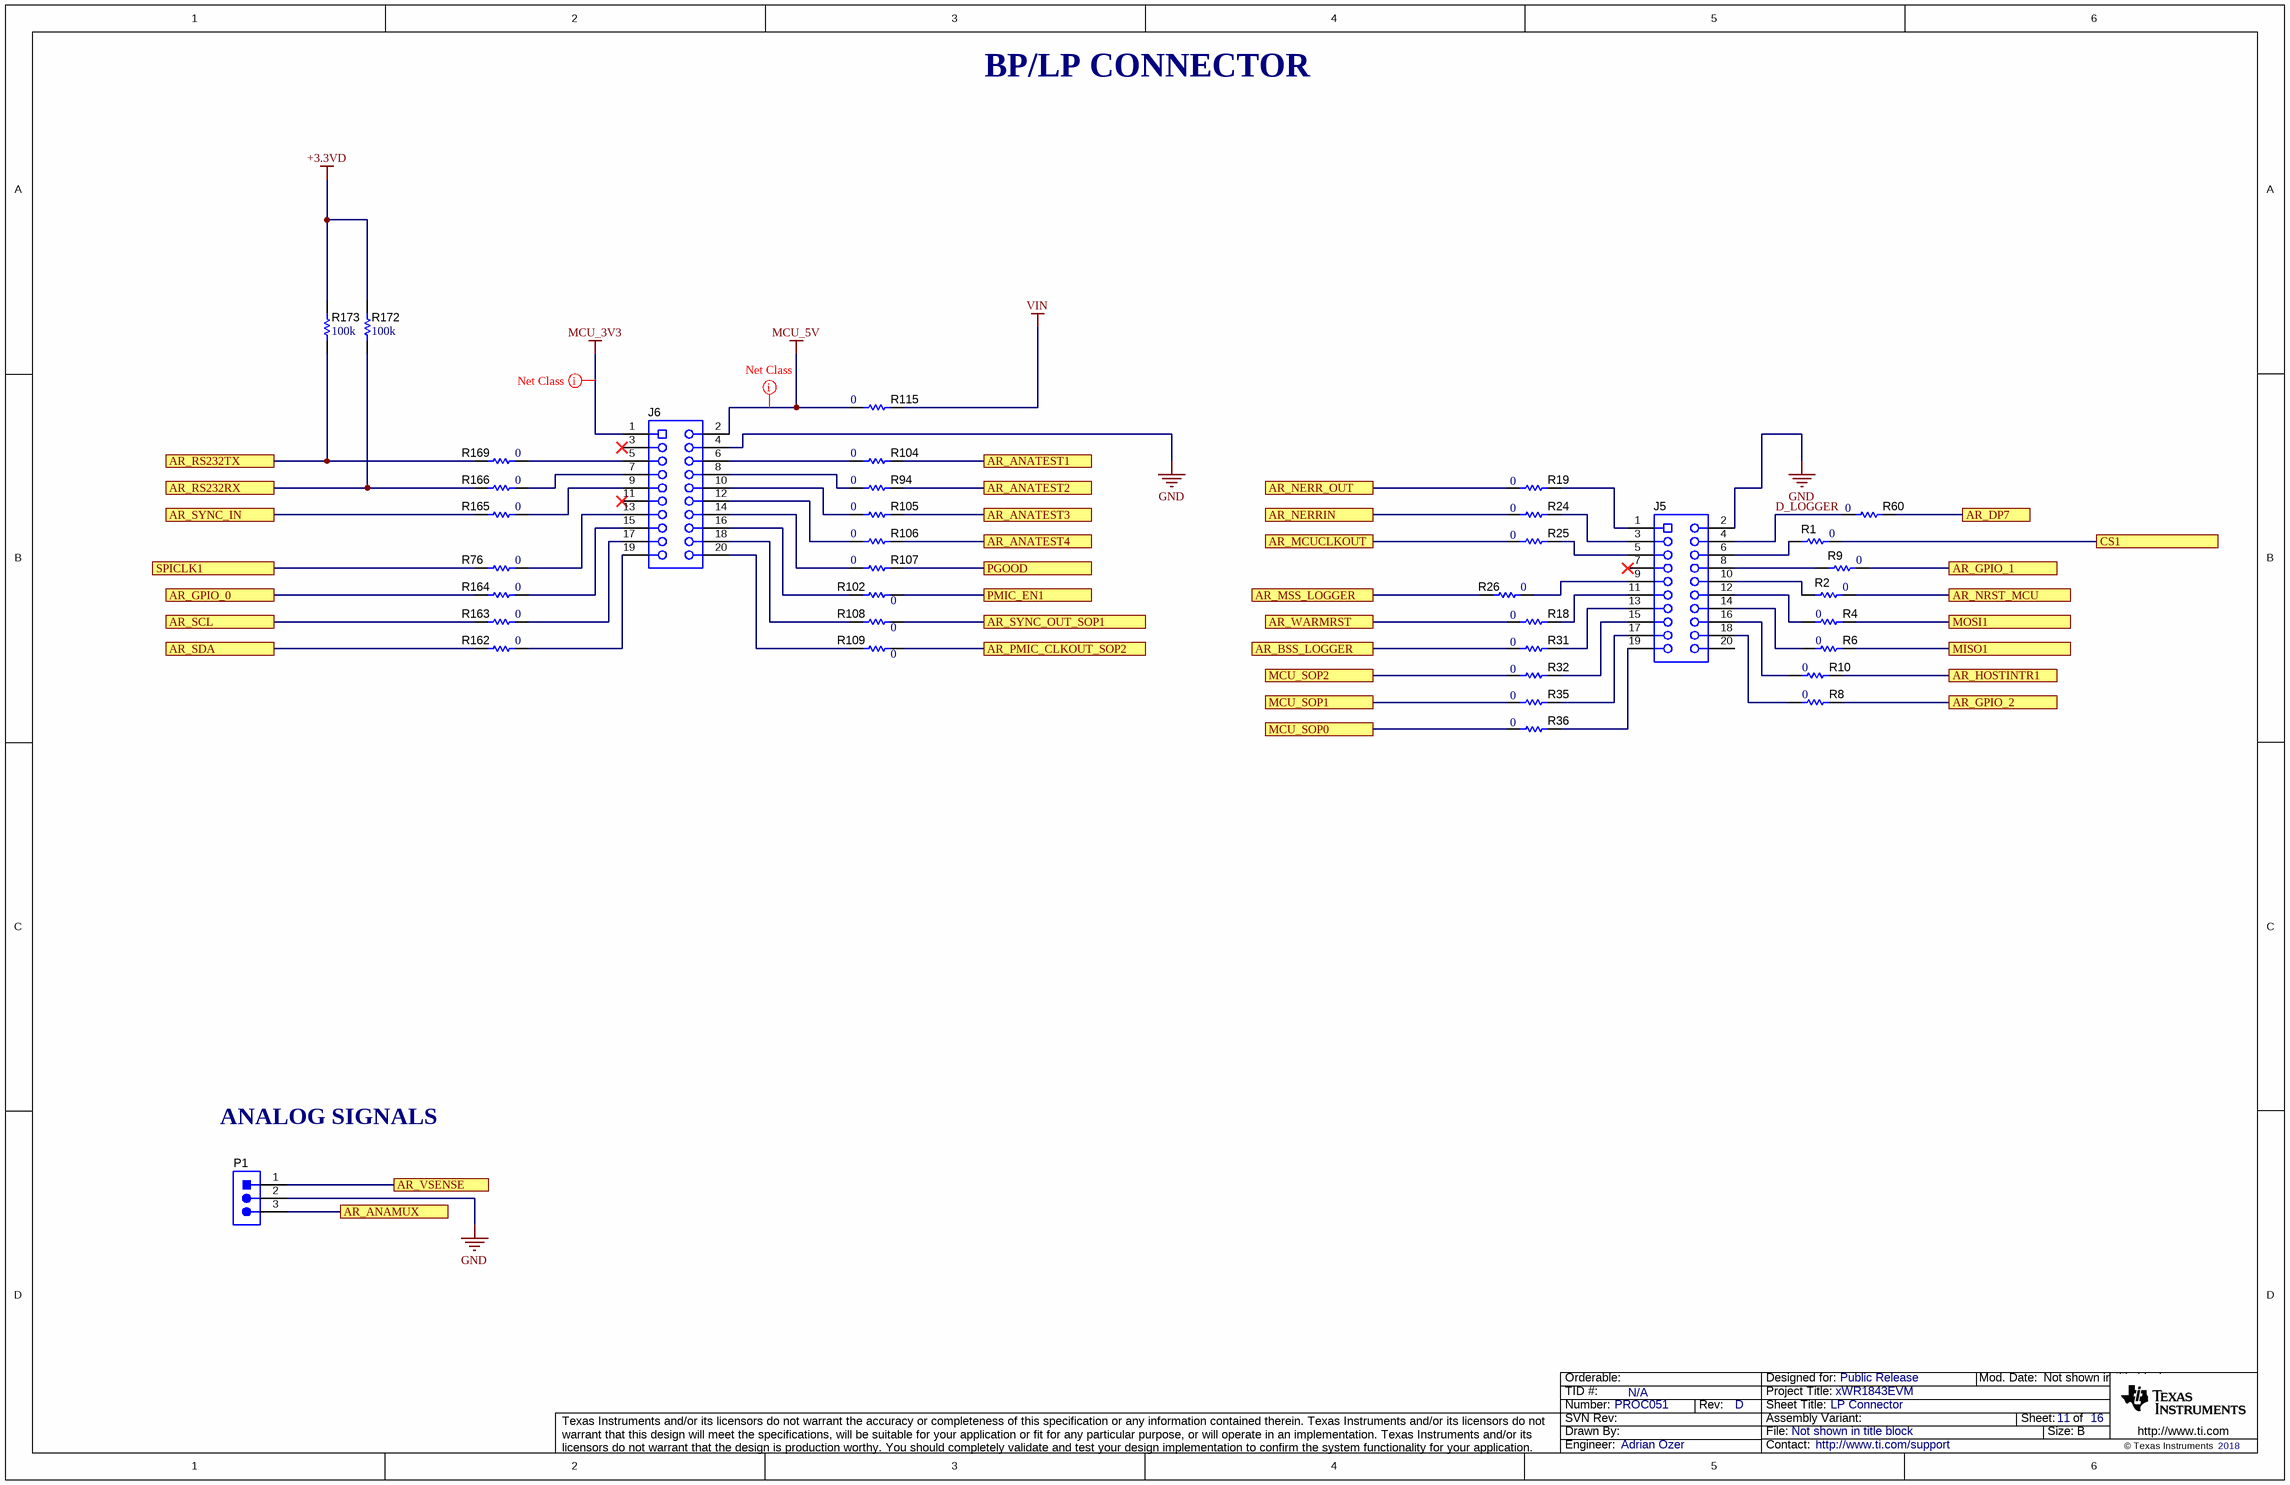
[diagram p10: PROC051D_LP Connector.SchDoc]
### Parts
J5  SSM-110-S-DV  [Samtec_SSM-110-x-DV]  (value not drawn)
J6  SSM-110-S-DV  [Samtec_SSM-110-x-DV]  (value not drawn)
P1  TSW-103-07-T-S  [Samtec_TSW-103-07-T-S]  (value not drawn)
R1  ValueDisplayed: 0  [0201_Silk]  (hidden comment: CRCW02010000Z0ED)
R2  ValueDisplayed: 0  [0201_Silk]  (hidden comment: CRCW02010000Z0ED)
R4  ValueDisplayed: 0  [0201_Silk]  (hidden comment: CRCW02010000Z0ED)
R6  ValueDisplayed: 0  [0201_Silk]  (hidden comment: CRCW02010000Z0ED)
R8  ValueDisplayed: 0  [0201_Silk]  (hidden comment: CRCW02010000Z0ED)
R9  ValueDisplayed: 0  [0201_Silk]  (hidden comment: CRCW02010000Z0ED)
R10  ValueDisplayed: 0  [0201_Silk]  (hidden comment: CRCW02010000Z0ED)
R18  ValueDisplayed: 0  [0201_Silk]  (hidden comment: CRCW02010000Z0ED)
R19  ValueDisplayed: 0  [0201_Silk]  (hidden comment: CRCW02010000Z0ED)
R24  ValueDisplayed: 0  [0201_Silk]  (hidden comment: CRCW02010000Z0ED)
R25  ValueDisplayed: 0  [0201_Silk]  (hidden comment: CRCW02010000Z0ED)
R26  ValueDisplayed: 0  [0201_Silk]  (hidden comment: CRCW02010000Z0ED)
R31  ValueDisplayed: 0  [0201_Silk]  (hidden comment: CRCW02010000Z0ED)
R32  ValueDisplayed: 0  [0201_Silk]  (hidden comment: CRCW02010000Z0ED)
R35  ValueDisplayed: 0  [0201_Silk]  (hidden comment: CRCW02010000Z0ED)
R36  ValueDisplayed: 0  [0201_Silk]  (hidden comment: CRCW02010000Z0ED)
R60  ValueDisplayed: 0  [0201_Silk]  (hidden comment: CRCW02010000Z0ED)
R76  ValueDisplayed: 0  [0201_Silk]  (hidden comment: CRCW02010000Z0ED)
R94  ValueDisplayed: 0  [0201_Silk]  (hidden comment: CRCW02010000Z0ED)
R102  ValueDisplayed: 0  [0201_Silk]  (hidden comment: CRCW02010000Z0ED)
R104  ValueDisplayed: 0  [0201_Silk]  (hidden comment: CRCW02010000Z0ED)
R105  ValueDisplayed: 0  [0201_Silk]  (hidden comment: CRCW02010000Z0ED)
R106  ValueDisplayed: 0  [0201_Silk]  (hidden comment: CRCW02010000Z0ED)
R107  ValueDisplayed: 0  [0402L]  (hidden comment: ERJ-2GE0R00X)
R108  ValueDisplayed: 0  [0201_Silk]  (hidden comment: CRCW02010000Z0ED)
R109  ValueDisplayed: 0  [0201_Silk]  (hidden comment: CRCW02010000Z0ED)
R115  ValueDisplayed: 0  [2010]  (hidden comment: CRCW20100000Z0EF)
R162  ValueDisplayed: 0  [0201_Silk]  (hidden comment: CRCW02010000Z0ED)
R163  ValueDisplayed: 0  [0201_Silk]  (hidden comment: CRCW02010000Z0ED)
R164  ValueDisplayed: 0  [0201_Silk]  (hidden comment: CRCW02010000Z0ED)
R165  ValueDisplayed: 0  [0201_Silk]  (hidden comment: CRCW02010000Z0ED)
R166  ValueDisplayed: 0  [0201_Silk]  (hidden comment: CRCW02010000Z0ED)
R169  ValueDisplayed: 0  [0201_Silk]  (hidden comment: CRCW02010000Z0ED)
R172  ValueDisplayed: 100k  [0402L]  (hidden comment: CRCW0402100KFKED)
R173  ValueDisplayed: 100k  [0402L]  (hidden comment: CRCW0402100KFKED)

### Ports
AR_ANAMUX, AR_ANATEST1, AR_ANATEST2, AR_ANATEST3, AR_ANATEST4, AR_BSS_LOGGER, AR_DP7, AR_GPIO_0, AR_GPIO_1, AR_GPIO_2, AR_HOSTINTR1, AR_MCUCLKOUT, AR_MSS_LOGGER, AR_NERR_OUT, AR_NERRIN, AR_NRST_MCU, AR_PMIC_CLKOUT_SOP2, AR_RS232RX, AR_RS232TX, AR_SCL, AR_SDA, AR_SYNC_IN, AR_SYNC_OUT_SOP1, AR_VSENSE, AR_WARMRST, CS1, MCU_SOP0, MCU_SOP1, MCU_SOP2, MISO1, MOSI1, PGOOD, PMIC_EN1, SPICLK1

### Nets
+3.3VD: R172.2 R173.2
GND: J5.2 J6.4 P1.2
MCU_3V3: J6.1
MCU_5V: J6.2 R115.1
VIN: R115.2
AR_ANAMUX: P1.3 ; port AR_ANAMUX
AR_ANATEST1: R104.2 ; port AR_ANATEST1
AR_ANATEST2: R94.2 ; port AR_ANATEST2
AR_ANATEST3: R105.2 ; port AR_ANATEST3
AR_ANATEST4: R106.2 ; port AR_ANATEST4
AR_BSS_LOGGER: R31.1 ; port AR_BSS_LOGGER
AR_DP7: R60.2 ; port AR_DP7
AR_GPIO_0: R164.1 ; port AR_GPIO_0
AR_GPIO_1: R9.2 ; port AR_GPIO_1
AR_GPIO_2: R8.2 ; port AR_GPIO_2
AR_HOSTINTR1: R10.2 ; port AR_HOSTINTR1
AR_MCUCLKOUT: R25.1 ; port AR_MCUCLKOUT
AR_MSS_LOGGER: R26.1 ; port AR_MSS_LOGGER
AR_NERR_OUT: R19.1 ; port AR_NERR_OUT
AR_NERRIN: R24.1 ; port AR_NERRIN
AR_NRST_MCU: R2.2 ; port AR_NRST_MCU
AR_PMIC_CLKOUT_SOP2: R109.2 ; port AR_PMIC_CLKOUT_SOP2
AR_RS232RX: R166.1 R172.1 ; port AR_RS232RX
AR_RS232TX: R169.1 R173.1 ; port AR_RS232TX
AR_SCL: R163.1 ; port AR_SCL
AR_SDA: R162.1 ; port AR_SDA
AR_SYNC_IN: R165.1 ; port AR_SYNC_IN
AR_SYNC_OUT_SOP1: R108.2 ; port AR_SYNC_OUT_SOP1
AR_VSENSE: P1.1 ; port AR_VSENSE
AR_WARMRST: R18.1 ; port AR_WARMRST
CS1: R1.2 ; port CS1
D_LOGGER: J5.4 R60.1
MCU_SOP0: R36.1 ; port MCU_SOP0
MCU_SOP1: R35.1 ; port MCU_SOP1
MCU_SOP2: R32.1 ; port MCU_SOP2
MISO1: R6.2 ; port MISO1
MOSI1: R4.2 ; port MOSI1
PGOOD: R107.2 ; port PGOOD
PMIC_EN1: R102.2 ; port PMIC_EN1
SPICLK1: R76.1 ; port SPICLK1
NetJ5_1: J5.1 R19.2
NetJ5_3: J5.3 R24.2
NetJ5_5: J5.5 R25.2
NetJ5_6: J5.6 R1.1
NetJ5_8: J5.8 R9.1
NetJ5_9: J5.9 R26.2
NetJ5_10: J5.10 R2.1
NetJ5_11: J5.11 R18.2
NetJ5_12: J5.12 R4.1
NetJ5_13: J5.13 R31.2
NetJ5_14: J5.14 R6.1
NetJ5_15: J5.15 R32.2
NetJ5_16: J5.16 R10.1
NetJ5_17: J5.17 R35.2
NetJ5_18: J5.18 R8.1
NetJ5_19: J5.19 R36.2
NetJ6_5: J6.5 R169.2
NetJ6_6: J6.6 R104.1
NetJ6_7: J6.7 R166.2
NetJ6_8: J6.8 R94.1
NetJ6_9: J6.9 R165.2
NetJ6_10: J6.10 R105.1
NetJ6_12: J6.12 R106.1
NetJ6_13: J6.13 R76.2
NetJ6_14: J6.14 R107.1
NetJ6_15: J6.15 R164.2
NetJ6_16: J6.16 R102.1
NetJ6_17: J6.17 R163.2
NetJ6_18: J6.18 R108.1
NetJ6_19: J6.19 R162.2
NetJ6_20: J6.20 R109.1

Not connected (* = marked no-connect by the designer): J5 7* 20; J6 3* 11*

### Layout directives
net class PWR: MCU_3V3, MCU_5V

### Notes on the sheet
- BP/LP CONNECTOR
- ANALOG SIGNALS

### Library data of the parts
J5 J6 = CMP-0078182-1: Receptacle, 2.54mm, 10x2, Gold with Tin tail, SMT; Manufacturer: Samtec; Pitch_mm: 2.54; Gender: Female; Cert_CSA: Y; Voltage_V: 405V; Current_A: 5.2A; Row_Count: 2; CompType: Socket Strip
P1 = CMP-0075530-2: Header, 2.54 mm, 3x1, Tin, TH; Manufacturer: Samtec; Pitch_mm: 2.54; Cert_VDE: N; Gender: Male; Cert_CSA: Y; Voltage_V: 550V; Green_REACh: Passed; Current_A: 6.3A; Green_Lifecycle: Active; Row_Count: 1
R1 R2 R4 R6 R8-R10 R18 R19 R24-R26 R31 R32 R35 R36 R60 R76 R94 R102 R104-R106 R108 R109 R162-R166 R169 = CMP-0027008-4: as R72 on sheet PROC051D_RST_LEDs
R107 = CMP-0026992-3: as R37 on sheet PROC051D_QSPI_Flash_Reference
R115 = CMP-0016044-3: as R34 on sheet PROC051D_HD Connector
R172 R173 = CMP-0025950-3: as R110 on sheet PROC051D_RST_LEDs

## Sheet PROC051D_XDS110 Interface_1A.SchDoc: XDS110 Interface_1A
size 431 x 279 mm; Date: Not shown in title block; ApprovedBy: Not shown in title block; CheckedBy: Not shown in title block; Author: Not shown in title block; CompanyName: Not shown in title block; Engineer: Not shown in title block; Organization: Not shown in title block; Address1: Not shown in title block; Address2: Not shown in title block; Address3: Not shown in title block; Address4: Not shown in title block; DocumentNumber: 12; Revision: Use project parameter SCH_Rev; SheetNumber: 12; SheetTotal: 16; PageSetup: Record=PageOptions¦CenterHorizontal=True¦CenterVertical=True¦PrintScale=1.00¦XCorrection=1.00¦YCorrection=1.00¦PrintKind=0¦BorderSize=5000000¦LeftOffset=0¦BottomOffset=0¦Orientation=2¦PaperLength=1000¦PaperWidth=1000¦Scale=100¦PaperSource=15¦PrintQuality=600¦MediaType=1¦DitherType=10¦PaperKind=Letter¦PrintScaleMode=1

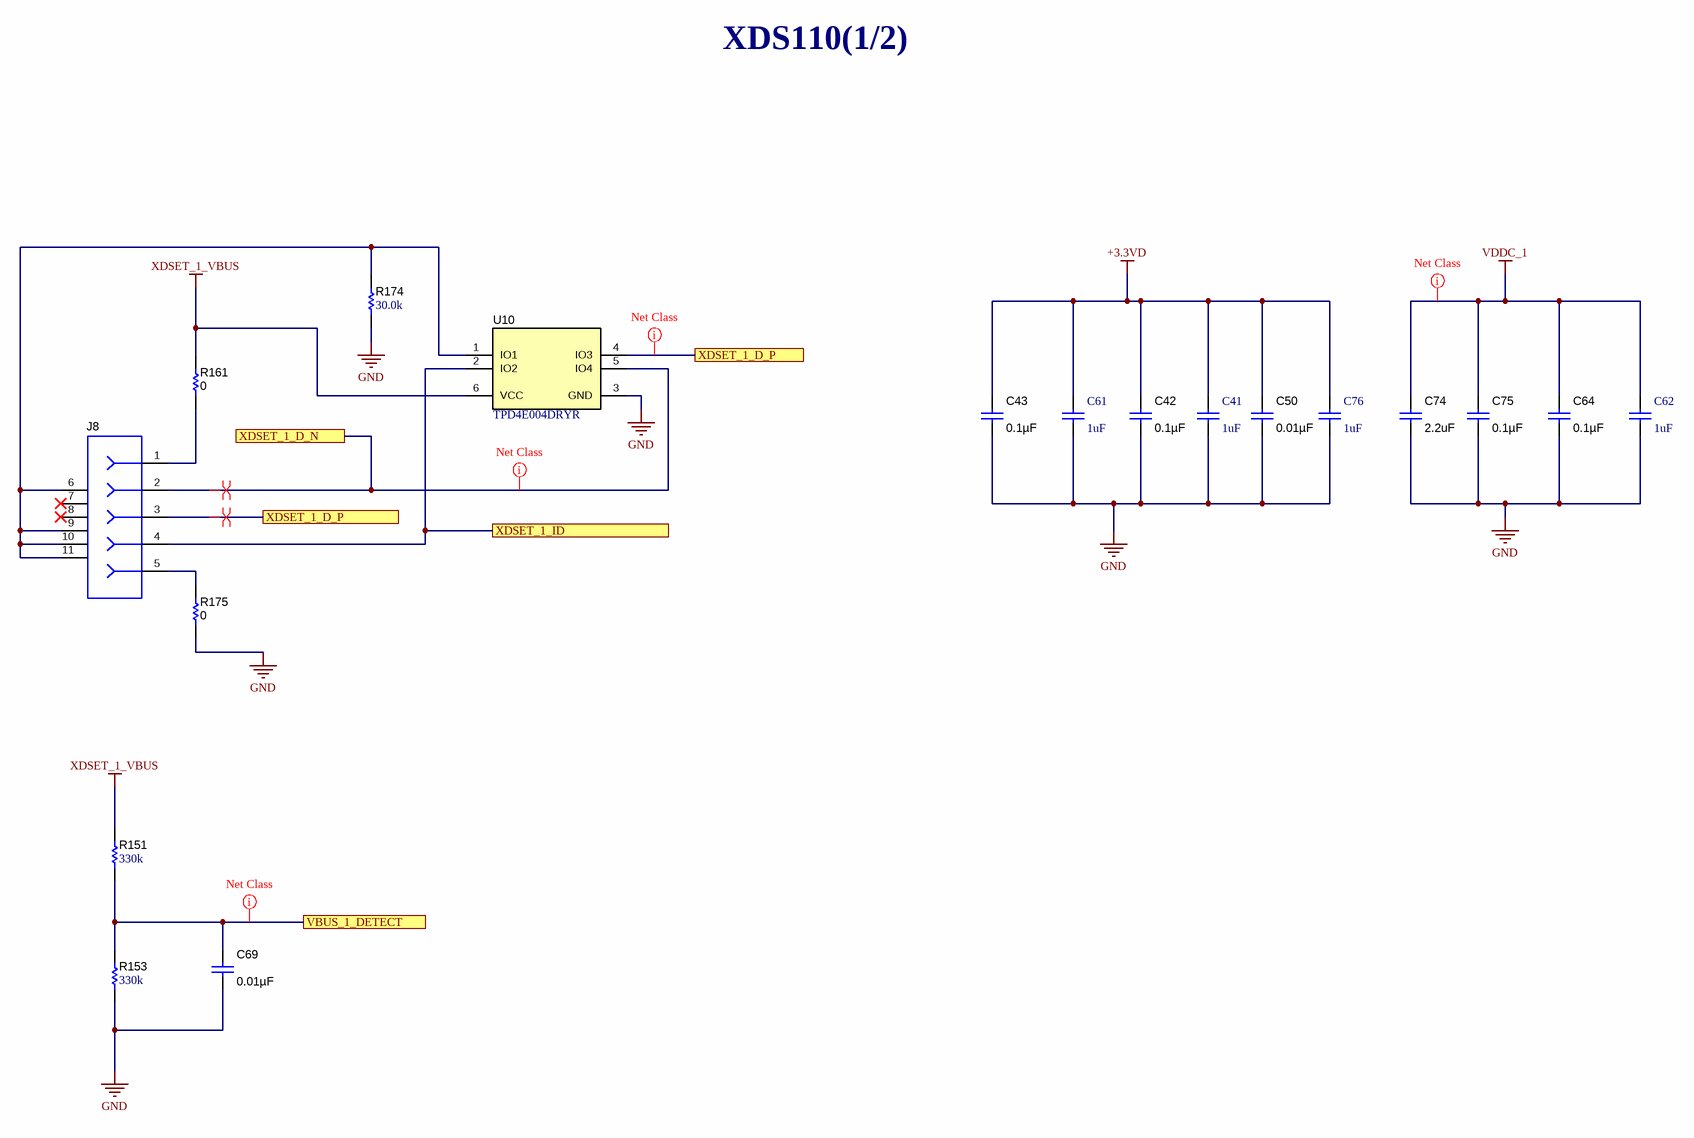
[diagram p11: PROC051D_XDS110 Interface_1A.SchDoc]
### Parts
C41  ValueDisplayed: 1uF  [0402_070]  (hidden comment: GCM155C71A105KE38D)
C42  ValueDisplayed: 0.1µF  [0402L]  (hidden comment: C0402C104K8RACTU)
C43  ValueDisplayed: 0.1µF  [0402L]  (hidden comment: C0402C104K8RACTU)
C50  ValueDisplayed: 0.01µF  [0402L]  (hidden comment: C0402C103K4RACTU)
C61  ValueDisplayed: 1uF  [0402_070]  (hidden comment: GCM155C71A105KE38D)
C62  ValueDisplayed: 1uF  [0402_070]  (hidden comment: GCM155C71A105KE38D)
C64  ValueDisplayed: 0.1µF  [0402L]  (hidden comment: C0402C104K8RACTU)
C69  ValueDisplayed: 0.01µF  [0402L]  (hidden comment: C0402C103K4RACTU)
C74  ValueDisplayed: 2.2uF  [0402_065L]  (hidden comment: C1005X7S1A225K050BC)
C75  ValueDisplayed: 0.1µF  [0402L]  (hidden comment: C0402C104K8RACTU)
C76  ValueDisplayed: 1uF  [0402_070]  (hidden comment: GCM155C71A105KE38D)
J8  105017-0001  [CONN_105017-0001]  (value not drawn)
R151  ValueDisplayed: 330k  [0402L]  (hidden comment: CRCW0402330KFKED)
R153  ValueDisplayed: 330k  [0402L]  (hidden comment: CRCW0402330KFKED)
R161  ValueDisplayed: 0  [0603]  (hidden comment: MCT06030Z0000ZP500)
R174  ValueDisplayed: 30.0k  [0402L]  (hidden comment: CRCW040230K0FKED)
R175  ValueDisplayed: 0  [0603]  (hidden comment: MCT06030Z0000ZP500)
U10  TPD4E004DRYR  [DRY0006A]

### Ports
VBUS_1_DETECT, XDSET_1_D_N, XDSET_1_D_P, XDSET_1_ID

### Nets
+3.3VD: C41.1 C42.2 C43.2 C50.2 C61.1 C76.1
GND: C41.2 C42.1 C43.1 C50.1 C61.2 C62.2 C64.1 C69.1 C74.1 C75.1 C76.2 R153.1 R174.1 R175.1 U10.3(GND)
VDDC_1: C62.1 C64.2 C74.2 C75.2
XDSET_1_VBUS: R151.2 R161.2 U10.6(VCC)
VBUS_1_DETECT: C69.2 R151.1 R153.2 ; port VBUS_1_DETECT
XDSET_1_D_N: J8.2 U10.5(IO4) ; port XDSET_1_D_N
XDSET_1_D_P: J8.3 U10.4(IO3) ; port XDSET_1_D_P
XDSET_1_ID: J8.4 U10.2(IO2) ; port XDSET_1_ID
NetJ8_1: J8.1 R161.1
NetJ8_5: J8.5 R175.2
NetJ8_6: J8.6 J8.9 J8.10 J8.11 R174.2 U10.1(IO1)

Not connected (* = marked no-connect by the designer): J8 7* 8*

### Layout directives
net class PWR: VBUS_1_DETECT, VDDC_1
net class USB: XDSET_1_D_N, XDSET_1_D_P
differential pair: XDSET_1_D_N, XDSET_1_D_P

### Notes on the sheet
- XDS110(1/2)

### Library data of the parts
C41 C61 C62 C76 = CMP-0006349-2: CAP, CERM, 1 uF, 10 V, +/- 10%, X7S, AEC-Q200 Grade 1, 0402; Manufacturer: MuRata; TaMin_C: -55°C; Polarized: N; SizeAreaWB_mm2: 3; Value1: Unknown; U/M: EA; Value: 1uF; TaMax_C: 125°C; SizeZ_mm: 0.7; SizeX_mm: 1; SizeY_mm: 0.5; Cap_Case: 0402; Value2: 10V; CompType: Capacitor; AEC Qualified: Y; Cap_F: 1µF; AEC Category: Q200
C42 C43 C64 C75 = CMP-0078241-1: CAP, CERM, 0.1 µF, 10 V,+/- 10%, X7R, 0402; Manufacturer: Kemet; TaMin_C: -55°C; Polarized: N; SizeAreaWB_mm2: 3; U/M: EA; Value: 0.1uF; TaMax_C: 125°C; SizeZ_mm: 0.6; SizeX_mm: 1; SizeY_mm: 0.5; Cap_Case: 0402; Value2: 10V; Cap_F: 100nF; AEC Category: Q200
C50 C69 = CMP-0078218-1: CAP, CERM, 0.01 µF, 16 V,+/- 10%, X7R, 0402; Manufacturer: Kemet; TaMin_C: -55°C; Polarized: N; Green_Lifecycle: Active; SizeAreaWB_mm2: 3; Green_REACh: Passed; U/M: EA; Value: 0.01uF; TaMax_C: 125°C; SizeZ_mm: 0.6; SizeX_mm: 1; SizeY_mm: 0.5; Cap_Case: 0402; Value2: 16V; Cap_F: 10nF; AEC Category: Q200
C74 = CMP-0006302-2: as C86 on sheet PROC051D_VPP_Supply
J8 = CMP-0055293-1: Connector, Receptacle, Micro-USB Type B, R/A, Bottom Mount SMT; Manufacturer: Molex; CNHeader: FALSE; Green_Lifecycle: Active; Gender: Female; Green_REACh: Passed; CompType: USB; CT: TRUE
R151 R153 = CMP-0078210-2: RES, 330 k, 1%, 0.063 W, AEC-Q200 Grade 0, 0402; Manufacturer: Vishay-Dale; SizeArea_mm2: 0.5; AEC Qualified: Y; AEC Category: Q200; Value: 330k; SizeZ_mm: 0.6; TempCo: 100 ppm/C; AEC Grade: 0; Power_W: 63mW; VDC_V: 50V; Value2: 0.063W; SizeX_mm: 1
R161 R175 = CMP-0025884-3: as R133 on sheet PROC051D_RST_LEDs
R174 = CMP-0078244-2: RES, 30.0 k, 1%, 0.063 W, AEC-Q200 Grade 0, 0402; Manufacturer: Vishay-Dale; Power_W: 63mW; Green_Lifecycle: Active; TempCo: 100 ppm/C; Value_Code: 30k0; Green_REACh: Passed; Value: 30.0k; Res_ohm: 30k; SizeX_mm: 1; SizeY_mm: 0.5; SizeZ_mm: 0.6; Value2: 0.063W; AEC Qualified: Y; VDC_V: 50V; AEC Grade: 0; AEC Category: Q200
U10 = CMP-0043115-3: 4-Channel ESD Protection Array for High-Speed Data Interfaces, DRY0006A (USON-6); Manufacturer: Texas Instruments; IO Leakage Current(nA): 1; USB High Speed: TRUE; IO Capacitance(Typ)(pF): 1.6; Eco-Plan: Green (RoHS & no Sb/Br); IEC 61000-4-2 Contact(+/- kV): 8; Breakdown Voltage(Min)(V): 6; IEC 61000-4-2 Air-Gap(+/- kV): 12; AEC Category: Q200; AEC Qualified: N; CompType: IC; SizeArea_mm2: 1.45; SizeAreaWB_mm2: 4.9; SizeX_mm: 1.0; SizeZ_mm: 0.6; Rating: Catalog

## Sheet PROC051D_XDS110 Interface_1B.SchDoc: XDS110 Interface_1B
size 431 x 279 mm; Date: Not shown in title block; ApprovedBy: Not shown in title block; CheckedBy: Not shown in title block; Author: Not shown in title block; CompanyName: Not shown in title block; Engineer: Not shown in title block; Organization: Not shown in title block; Address1: Not shown in title block; Address2: Not shown in title block; Address3: Not shown in title block; Address4: Not shown in title block; DocumentNumber: 13; Revision: Use project parameter SCH_Rev; SheetNumber: 13; SheetTotal: 16; PageSetup: Record=PageOptions¦CenterHorizontal=True¦CenterVertical=True¦PrintScale=1.00¦XCorrection=1.00¦YCorrection=1.00¦PrintKind=0¦BorderSize=5000000¦LeftOffset=0¦BottomOffset=0¦Orientation=2¦PaperLength=1000¦PaperWidth=1000¦Scale=100¦PaperSource=15¦PrintQuality=600¦MediaType=1¦DitherType=10¦PaperKind=Letter¦PrintScaleMode=1

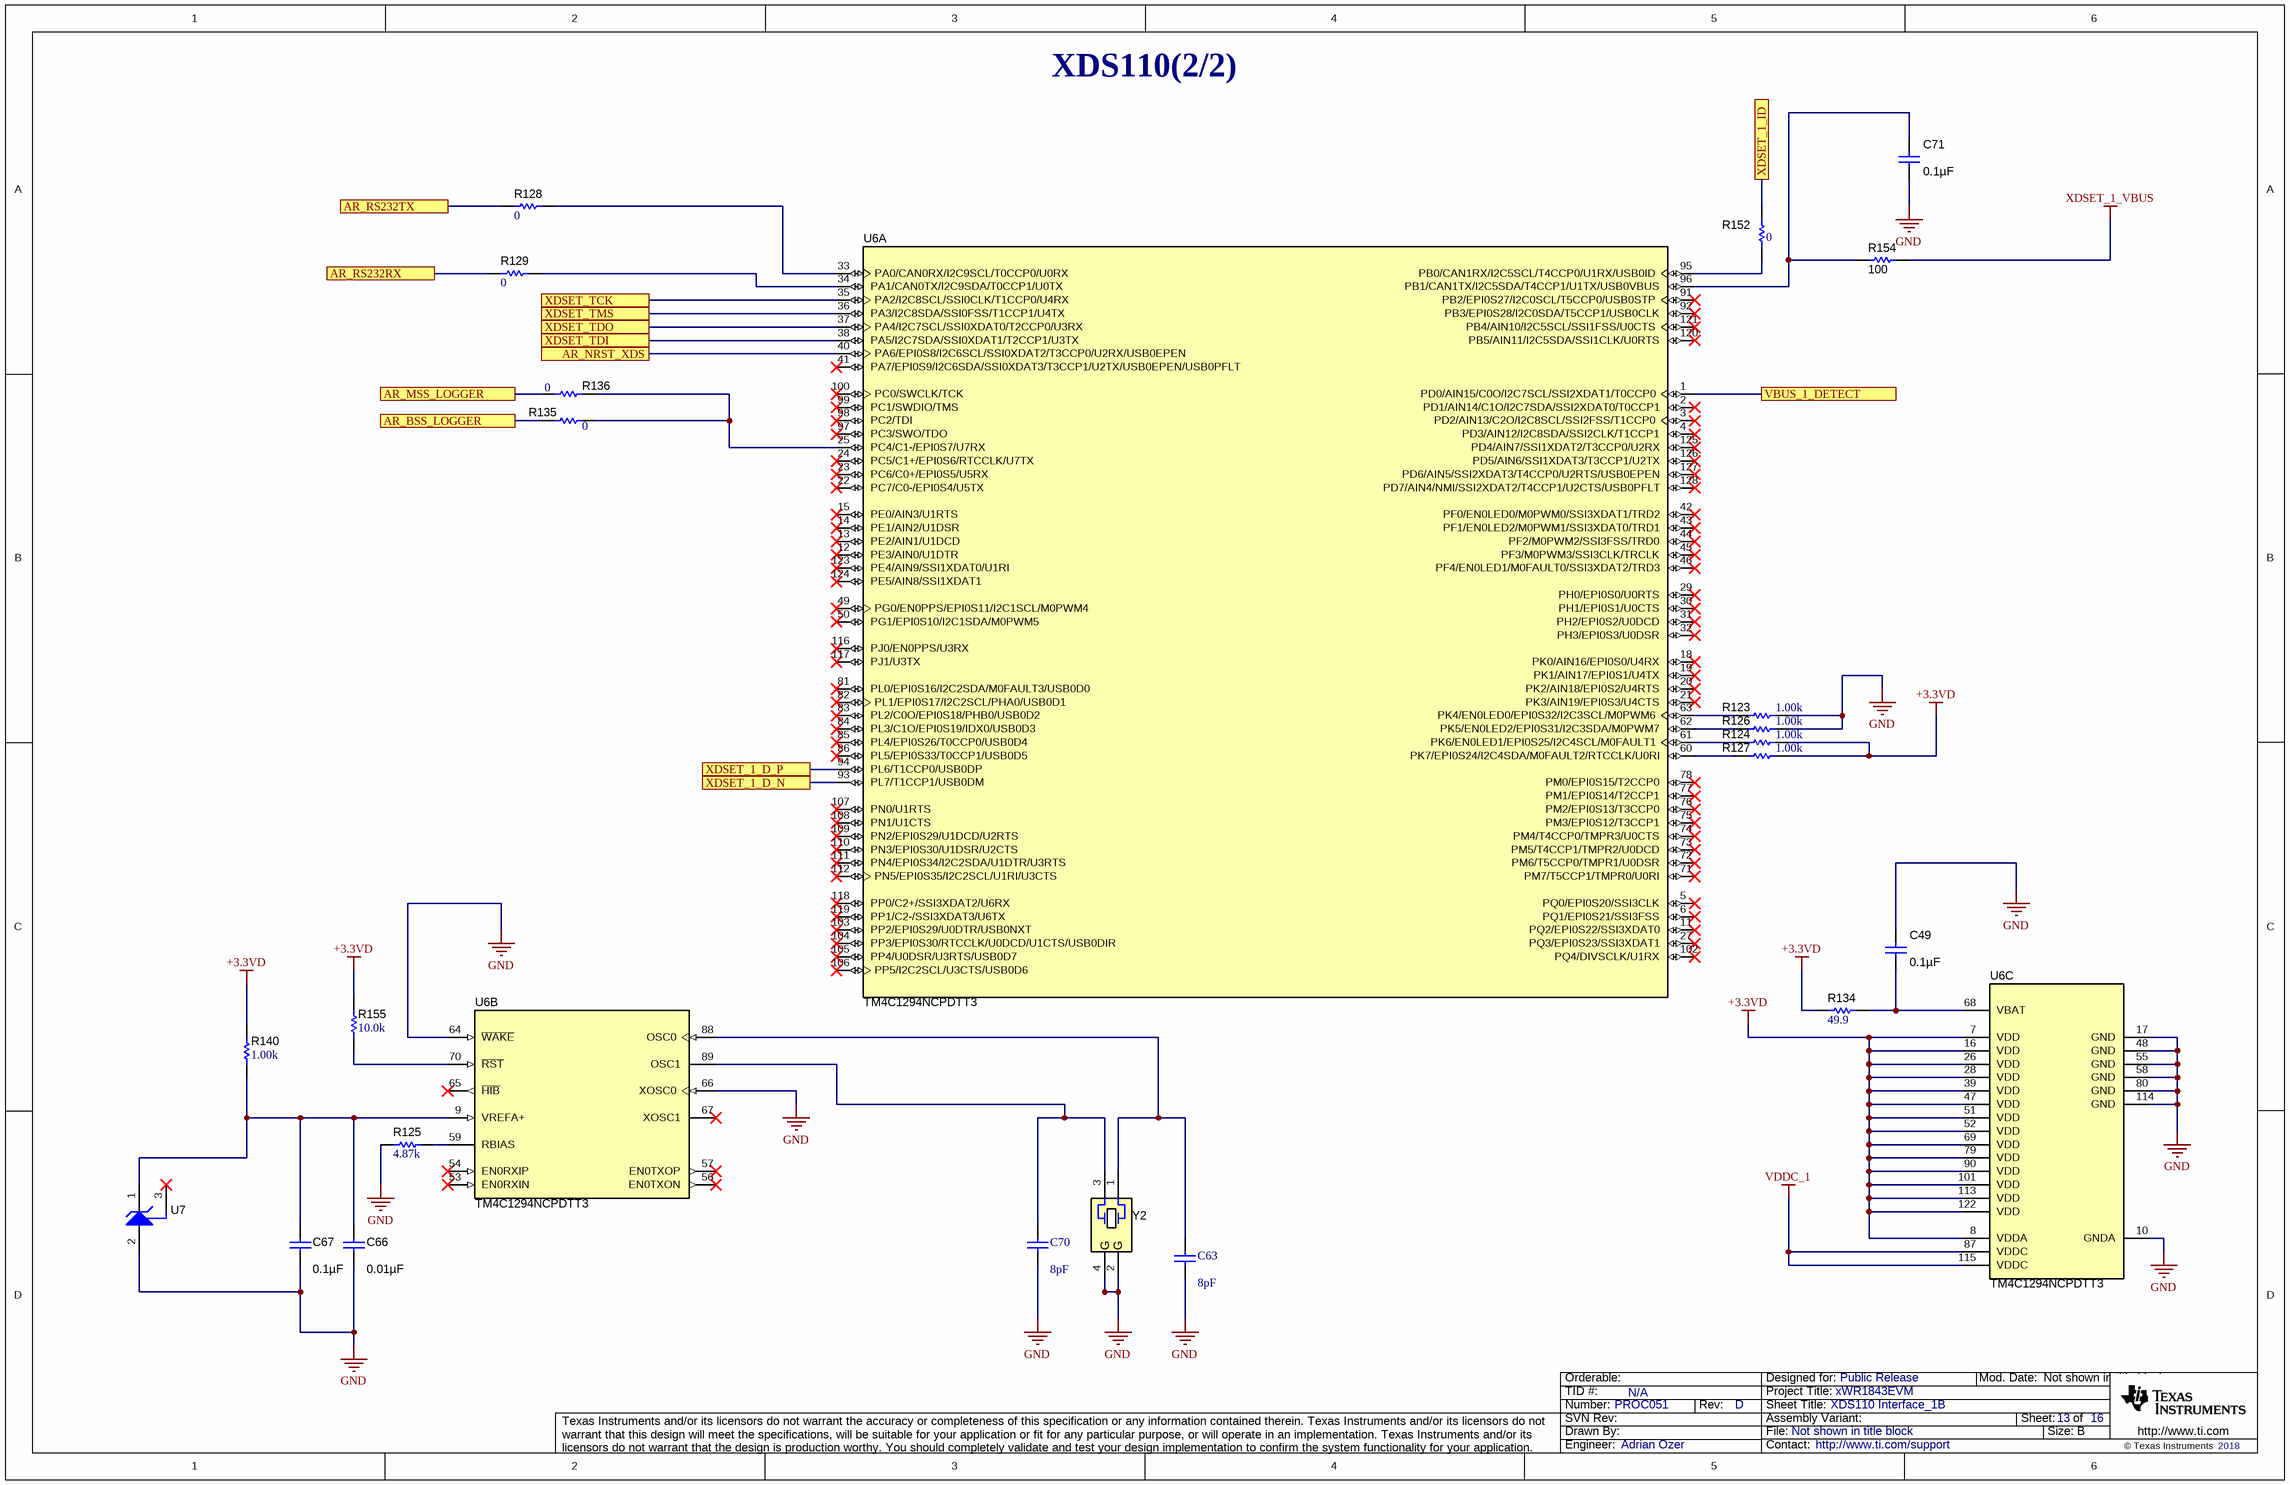
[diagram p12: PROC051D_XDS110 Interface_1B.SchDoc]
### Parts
C49  ValueDisplayed: 0.1µF  [0402L]  (hidden comment: C0402C104K8RACTU)
C63  Cap_F: 8pF  [0402L]  (hidden comment: GCM1555C1H8R0DA16D)
C66  ValueDisplayed: 0.01µF  [0402L]  (hidden comment: C0402C103K4RACTU)
C67  ValueDisplayed: 0.1µF  [0402L]  (hidden comment: C0402C104K8RACTU)
C70  Cap_F: 8pF  [0402L]  (hidden comment: GCM1555C1H8R0DA16D)
C71  ValueDisplayed: 0.1µF  [0402L]  (hidden comment: C0402C104K8RACTU)
R123  ValueDisplayed: 1.00k  [0402L]  (hidden comment: CRCW04021K00FKED)
R124  ValueDisplayed: 1.00k  [0402L]  (hidden comment: CRCW04021K00FKED)
R125  ValueDisplayed: 4.87k  [0402L]  (hidden comment: CRCW04024K87FKED)
R126  ValueDisplayed: 1.00k  [0402L]  (hidden comment: CRCW04021K00FKED)
R127  ValueDisplayed: 1.00k  [0402L]  (hidden comment: CRCW04021K00FKED)
R128  ValueDisplayed: 0  [0402L]  (hidden comment: ERJ-2GE0R00X)
R129  ValueDisplayed: 0  [0402L]  (hidden comment: ERJ-2GE0R00X)
R134  ValueDisplayed: 49.9  [0402L]  (hidden comment: CRCW040249R9FKED)
R135  ValueDisplayed: 0  [0201_Silk]  (hidden comment: CRCW02010000Z0ED)
R136  ValueDisplayed: 0  [0201_Silk]  (hidden comment: CRCW02010000Z0ED)
R140  ValueDisplayed: 1.00k  [0402L]  (hidden comment: CRCW04021K00FKED)
R152  ValueDisplayed: 0  [0402L]  (hidden comment: ERJ-2GE0R00X)
R154  ValueDisplayed: 100  [0402L]  (hidden comment: ERJ-2GEJ101X)
R155  ValueDisplayed: 10.0k  [0402L]  (hidden comment: CRCW040210K0FKED)
U6  TM4C1294NCPDTT3  [PDT0128A]  (parts A,B,C of 3)
U7  LM4040C25QDBZR  [DBZ0003A_N]  (value not drawn)
Y2  NX3225SA-16.000M-STD-CRS-2  [NDK_NX3225SA]  (value not drawn)

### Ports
AR_BSS_LOGGER, AR_MSS_LOGGER, AR_NRST_XDS, AR_RS232RX, AR_RS232TX, VBUS_1_DETECT, XDSET_1_D_N, XDSET_1_D_P, XDSET_1_ID, XDSET_TCK, XDSET_TDI, XDSET_TDO, XDSET_TMS

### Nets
+3.3VD: R124.2 R127.2 R134.2 R140.2 R155.2 U6.7(VDD) U6.8(VDDA) U6.16(VDD) U6.26(VDD) U6.28(VDD) U6.39(VDD) U6.47(VDD) U6.51(VDD) U6.52(VDD) U6.69(VDD) U6.79(VDD) U6.90(VDD) U6.101(VDD) U6.113(VDD) U6.122(VDD)
GND: C49.1 C63.2 C66.1 C67.1 C70.2 C71.1 R123.2 R125.1 R126.2 U6.10(GNDA) U6.17(GND) U6.48(GND) U6.55(GND) U6.58(GND) U6.64(~{WAKE}) U6.66(XOSC0) U6.80(GND) U6.114(GND) U7.2(ANODE) Y2.2(GND) Y2.4(GND)
VDDC_1: U6.87(VDDC) U6.115(VDDC)
XDSET_1_VBUS: R154.2
AR_BSS_LOGGER: R135.1 ; port AR_BSS_LOGGER
AR_MSS_LOGGER: R136.1 ; port AR_MSS_LOGGER
AR_NRST_XDS: U6.40(PA6/EPI0S8/I2C6SCL/SSI0XDAT2/T3CCP0/U2RX/USB0EPEN) ; port AR_NRST_XDS
AR_RS232RX: R129.1 ; port AR_RS232RX
AR_RS232TX: R128.1 ; port AR_RS232TX
VBUS_1_DETECT: U6.1(PD0/AIN15/C0O/I2C7SCL/SSI2XDAT1/T0CCP0) ; port VBUS_1_DETECT
XDSET_1_D_N: U6.93(PL7/T1CCP1/USB0DM) ; port XDSET_1_D_N
XDSET_1_D_P: U6.94(PL6/T1CCP0/USB0DP) ; port XDSET_1_D_P
XDSET_1_ID: R152.2 ; port XDSET_1_ID
XDSET_TCK: U6.35(PA2/I2C8SCL/SSI0CLK/T1CCP0/U4RX) ; port XDSET_TCK
XDSET_TDI: U6.38(PA5/I2C7SDA/SSI0XDAT1/T2CCP1/U3TX) ; port XDSET_TDI
XDSET_TDO: U6.37(PA4/I2C7SCL/SSI0XDAT0/T2CCP0/U3RX) ; port XDSET_TDO
XDSET_TMS: U6.36(PA3/I2C8SDA/SSI0FSS/T1CCP1/U4TX) ; port XDSET_TMS
NetC49_2: C49.2 R134.1 U6.68(VBAT)
NetC63_1: C63.1 U6.88(OSC0) Y2.1
NetC66_2: C66.2 C67.2 R140.1 U6.9(VREFA+) U7.1(CATHODE)
NetC70_1: C70.1 U6.89(OSC1) Y2.3
NetC71_2: C71.2 R154.1 U6.96(PB1/CAN1TX/I2C5SDA/T4CCP1/U1TX/USB0VBUS)
NetR123_1: R123.1 U6.63(PK4/EN0LED0/EPI0S32/I2C3SCL/M0PWM6)
NetR124_1: R124.1 U6.61(PK6/EN0LED1/EPI0S25/I2C4SCL/M0FAULT1)
NetR125_2: R125.2 U6.59(RBIAS)
NetR126_1: R126.1 U6.62(PK5/EN0LED2/EPI0S31/I2C3SDA/M0PWM7)
NetR127_1: R127.1 U6.60(PK7/EPI0S24/I2C4SDA/M0FAULT2/RTCCLK/U0RI)
NetR128_2: R128.2 U6.33(PA0/CAN0RX/I2C9SCL/T0CCP0/U0RX)
NetR129_2: R129.2 U6.34(PA1/CAN0TX/I2C9SDA/T0CCP1/U0TX)
NetR135_2: R135.2 R136.2 U6.25(PC4/C1-/EPI0S7/U7RX)
NetR152_1: R152.1 U6.95(PB0/CAN1RX/I2C5SCL/T4CCP0/U1RX/USB0ID)
NetR155_1: R155.1 U6.70(~{RST})

Not connected (* = marked no-connect by the designer): U6 2(PD1/AIN14/C1O/I2C7SDA/SSI2XDAT0/T0CCP1)* 3(PD2/AIN13/C2O/I2C8SCL/SSI2FSS/T1CCP0)* 4(PD3/AIN12/I2C8SDA/SSI2CLK/T1CCP1)* 5(PQ0/EPI0S20/SSI3CLK)* 6(PQ1/EPI0S21/SSI3FSS)* 11(PQ2/EPI0S22/SSI3XDAT0)* 12(PE3/AIN0/U1DTR)* 13(PE2/AIN1/U1DCD)* 14(PE1/AIN2/U1DSR)* 15(PE0/AIN3/U1RTS)* 18(PK0/AIN16/EPI0S0/U4RX)* 19(PK1/AIN17/EPI0S1/U4TX)* 20(PK2/AIN18/EPI0S2/U4RTS)* 21(PK3/AIN19/EPI0S3/U4CTS)* 22(PC7/C0-/EPI0S4/U5TX)* 23(PC6/C0+/EPI0S5/U5RX)* 24(PC5/C1+/EPI0S6/RTCCLK/U7TX)* 27(PQ3/EPI0S23/SSI3XDAT1)* 29(PH0/EPI0S0/U0RTS)* 30(PH1/EPI0S1/U0CTS)* 31(PH2/EPI0S2/U0DCD)* 32(PH3/EPI0S3/U0DSR)* 41(PA7/EPI0S9/I2C6SDA/SSI0XDAT3/T3CCP1/U2TX/USB0EPEN/USB0PFLT)* 42(PF0/EN0LED0/M0PWM0/SSI3XDAT1/TRD2)* 43(PF1/EN0LED2/M0PWM1/SSI3XDAT0/TRD1)* 44(PF2/M0PWM2/SSI3FSS/TRD0)* 45(PF3/M0PWM3/SSI3CLK/TRCLK)* 46(PF4/EN0LED1/M0FAULT0/SSI3XDAT2/TRD3)* 49(PG0/EN0PPS/EPI0S11/I2C1SCL/M0PWM4)* 50(PG1/EPI0S10/I2C1SDA/M0PWM5)* 53(EN0RXIN)* 54(EN0RXIP)* 56(EN0TXON)* 57(EN0TXOP)* 65(~{HIB})* 67(XOSC1)* 71(PM7/T5CCP1/TMPR0/U0RI)* 72(PM6/T5CCP0/TMPR1/U0DSR)* 73(PM5/T4CCP1/TMPR2/U0DCD)* 74(PM4/T4CCP0/TMPR3/U0CTS)* 75(PM3/EPI0S12/T3CCP1)* 76(PM2/EPI0S13/T3CCP0)* 77(PM1/EPI0S14/T2CCP1)* 78(PM0/EPI0S15/T2CCP0)* 81(PL0/EPI0S16/I2C2SDA/M0FAULT3/USB0D0)* 82(PL1/EPI0S17/I2C2SCL/PHA0/USB0D1)* 83(PL2/C0O/EPI0S18/PHB0/USB0D2)* 84(PL3/C1O/EPI0S19/IDX0/USB0D3)* 85(PL4/EPI0S26/T0CCP0/USB0D4)* 86(PL5/EPI0S33/T0CCP1/USB0D5)* 91(PB2/EPI0S27/I2C0SCL/T5CCP0/USB0STP)* 92(PB3/EPI0S28/I2C0SDA/T5CCP1/USB0CLK)* 97(PC3/SWO/TDO)* 98(PC2/TDI)* 99(PC1/SWDIO/TMS)* 100(PC0/SWCLK/TCK)* 102(PQ4/DIVSCLK/U1RX)* 103(PP2/EPI0S29/U0DTR/USB0NXT)* 104(PP3/EPI0S30/RTCCLK/U0DCD/U1CTS/USB0DIR)* 105(PP4/U0DSR/U3RTS/USB0D7)* 106(PP5/I2C2SCL/U3CTS/USB0D6)* 107(PN0/U1RTS)* 108(PN1/U1CTS)* 109(PN2/EPI0S29/U1DCD/U2RTS)* 110(PN3/EPI0S30/U1DSR/U2CTS)* 111(PN4/EPI0S34/I2C2SDA/U1DTR/U3RTS)* 112(PN5/EPI0S35/I2C2SCL/U1RI/U3CTS)* 116(PJ0/EN0PPS/U3RX)* 117(PJ1/U3TX)* 118(PP0/C2+/SSI3XDAT2/U6RX)* 119(PP1/C2-/SSI3XDAT3/U6TX)* 120(PB5/AIN11/I2C5SDA/SSI1CLK/U0RTS)* 121(PB4/AIN10/I2C5SCL/SSI1FSS/U0CTS)* 123(PE4/AIN9/SSI1XDAT0/U1RI)* 124(PE5/AIN8/SSI1XDAT1)* 125(PD4/AIN7/SSI1XDAT2/T3CCP0/U2RX)* 126(PD5/AIN6/SSI1XDAT3/T3CCP1/U2TX)* 127(PD6/AIN5/SSI2XDAT3/T4CCP0/U2RTS/USB0EPEN)* 128(PD7/AIN4/NMI/SSI2XDAT2/T4CCP1/U2CTS/USB0PFLT)*; U7 3(NC)*

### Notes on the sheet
- XDS110(2/2)

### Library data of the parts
C49 = CMP-0078241-1: CAP, CERM, 0.1 µF, 10 V,+/- 10%, X7R, 0402; Manufacturer: Kemet; TaMin_C: -55°C; Polarized: N; SizeAreaWB_mm2: 3; U/M: EA; Value: 0.1uF; TaMax_C: 125°C; SizeZ_mm: 0.6; SizeX_mm: 1; SizeY_mm: 0.5; Cap_Case: 0402; Value2: 10V; CompType: Capacitor; Cap_F: 100nF; AEC Category: Q200
C63 C70 = CMP-0087060-3: Cap Ceramic 8pF 50V C0G 0.5pF SMD 0402 125C Paper T/R; Manufacturer: Murata Electronics North America; AEC Qualified: Yes; TempCo: 30ppm/°C; AEC Grade: Grade 1; SizeZ_mm: 0.55mm
C66 = CMP-0078218-1: as C50 on sheet PROC051D_XDS110 Interface_1A
C67 C71 = CMP-0078241-1: as C42 on sheet PROC051D_XDS110 Interface_1A
R123 R124 R126 R127 R140 = CMP-0026071-3: RES, 1.00 k, 1%, 0.063 W, AEC-Q200 Grade 0, 0402; Manufacturer: Vishay-Dale; Power_W: 63mW; TempCo: 100 ppm/C; Value_Code: 1k00; Value: 1.00k; EIA_Code: E96; Res_ohm: 1k; SizeX_mm: 1; SizeY_mm: 0.5; SizeZ_mm: 0.6; Value2: 0.063W; AEC Qualified: Y; VDC_V: 50V; AEC Category: Q200; AEC Grade: 0
R125 = CMP-0026413-2: RES, 4.87 k, 1%, 0.063 W, AEC-Q200 Grade 0, 0402; Manufacturer: Vishay-Dale; Power_W: 63mW; TempCo: 100 ppm/C; Value_Code: 4k87; Value: 4.87k; EIA_Code: E96; SizeX_mm: 1; SizeY_mm: 0.5; SizeZ_mm: 0.6; Value2: 0.063W; AEC Qualified: Y; VDC_V: 50V; AEC Category: Q200; AEC Grade: 0
R128 R129 R152 = CMP-0026992-3: as R37 on sheet PROC051D_QSPI_Flash_Reference
R134 = CMP-0026404-2: RES, 49.9, 1%, 0.063 W, AEC-Q200 Grade 0, 0402; Manufacturer: Vishay-Dale; Power_W: 63mW; TempCo: 100 ppm/C; Value_Code: 49R9; Value: 49.9; EIA_Code: E96; SizeX_mm: 1; SizeY_mm: 0.5; SizeZ_mm: 0.6; Value2: 0.063W; AEC Qualified: Y; VDC_V: 50V; AEC Category: Q200; AEC Grade: 0
R135 R136 = CMP-0027008-4: as R72 on sheet PROC051D_RST_LEDs
R154 = CMP-0026993-2: as R68 on sheet PROC051D_RST_LEDs
R155 = CMP-0025958-3: as R41 on sheet PROC051D_QSPI_Flash_Reference
U6 = CMP-0029856-2: Tiva C Series Microcontroller, 1024 KB Flash, 256 KB SRAM, 12 Bit, 20 Channels, -40 to 105 degC, 128-Pin TQFP (PDT), Green (RoHS & no Sb/Br), Tray; Manufacturer: Texas Instruments; ADC Channels: 20; CPU: ARM Cortex-M4; Flash: 1024 KB; ADC Resolution: 12 Bits; Max Speed: 120 MHz; SRAM: 256 KB; SizeAreaWB_mm2: 324.0; SizeArea_mm2: 256.0; SizeX_mm: 16.0; SizeZ_mm: 1.2; CompType: IC
U7 = CMP-0033001-1: Precision Micropower Shunt Voltage Reference, 0.5% accuracy, 2.5 V, 15 ppm / degC, 15 mA, -40 to 125 degC, 3-pin SOT-23 (DBZ), Green (RoHS & no Sb/Br); Manufacturer: Texas Instruments; Initial Accuracy @ 25/deg C(%): 0.5; Temp Coeff(Typ)(ppm/ degree C): 15; Temp Coeff(Max)(ppm/ degree C): 100; Rating: Catalog; Min Iz for Regulation(uA): 75; VO(V): 2.5
Y2 = CMP-0078214-2: Crystal, 16 MHz, 15 ppm, 8 pF, AEC-Q200 Grade 1, SMD; Manufacturer: NDK; TaMin_C: -40°C; Frequency Tolerance: 10 ppm; Frequency Stability: 150 ppm; Load Capacitance: 7.36 pF; Frequency_Fixed: 16MHz; TaMax_C: 125°C; AEC Qualified: N; AEC Grade: 1; AEC Category: Q200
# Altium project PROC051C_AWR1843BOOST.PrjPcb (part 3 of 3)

## Sheet PROC051D_CAN_Interface.SchDoc: CAN Interface
size 431 x 279 mm; Date: Not shown in title block; ApprovedBy: Not shown in title block; CheckedBy: Not shown in title block; Author: Not shown in title block; CompanyName: Not shown in title block; Engineer: Not shown in title block; Organization: Not shown in title block; Address1: Not shown in title block; Address2: Not shown in title block; Address3: Not shown in title block; Address4: Not shown in title block; DocumentNumber: 14; Revision: Use project parameter SCH_Rev; SheetNumber: 14; SheetTotal: 16; PageSetup: Record=PageOptions¦CenterHorizontal=True¦CenterVertical=True¦PrintScale=1.00¦XCorrection=1.00¦YCorrection=1.00¦PrintKind=0¦BorderSize=5000000¦LeftOffset=0¦BottomOffset=0¦Orientation=2¦PaperLength=1000¦PaperWidth=1000¦Scale=100¦PaperSource=15¦PrintQuality=600¦MediaType=1¦DitherType=10¦PaperKind=Letter¦PrintScaleMode=1

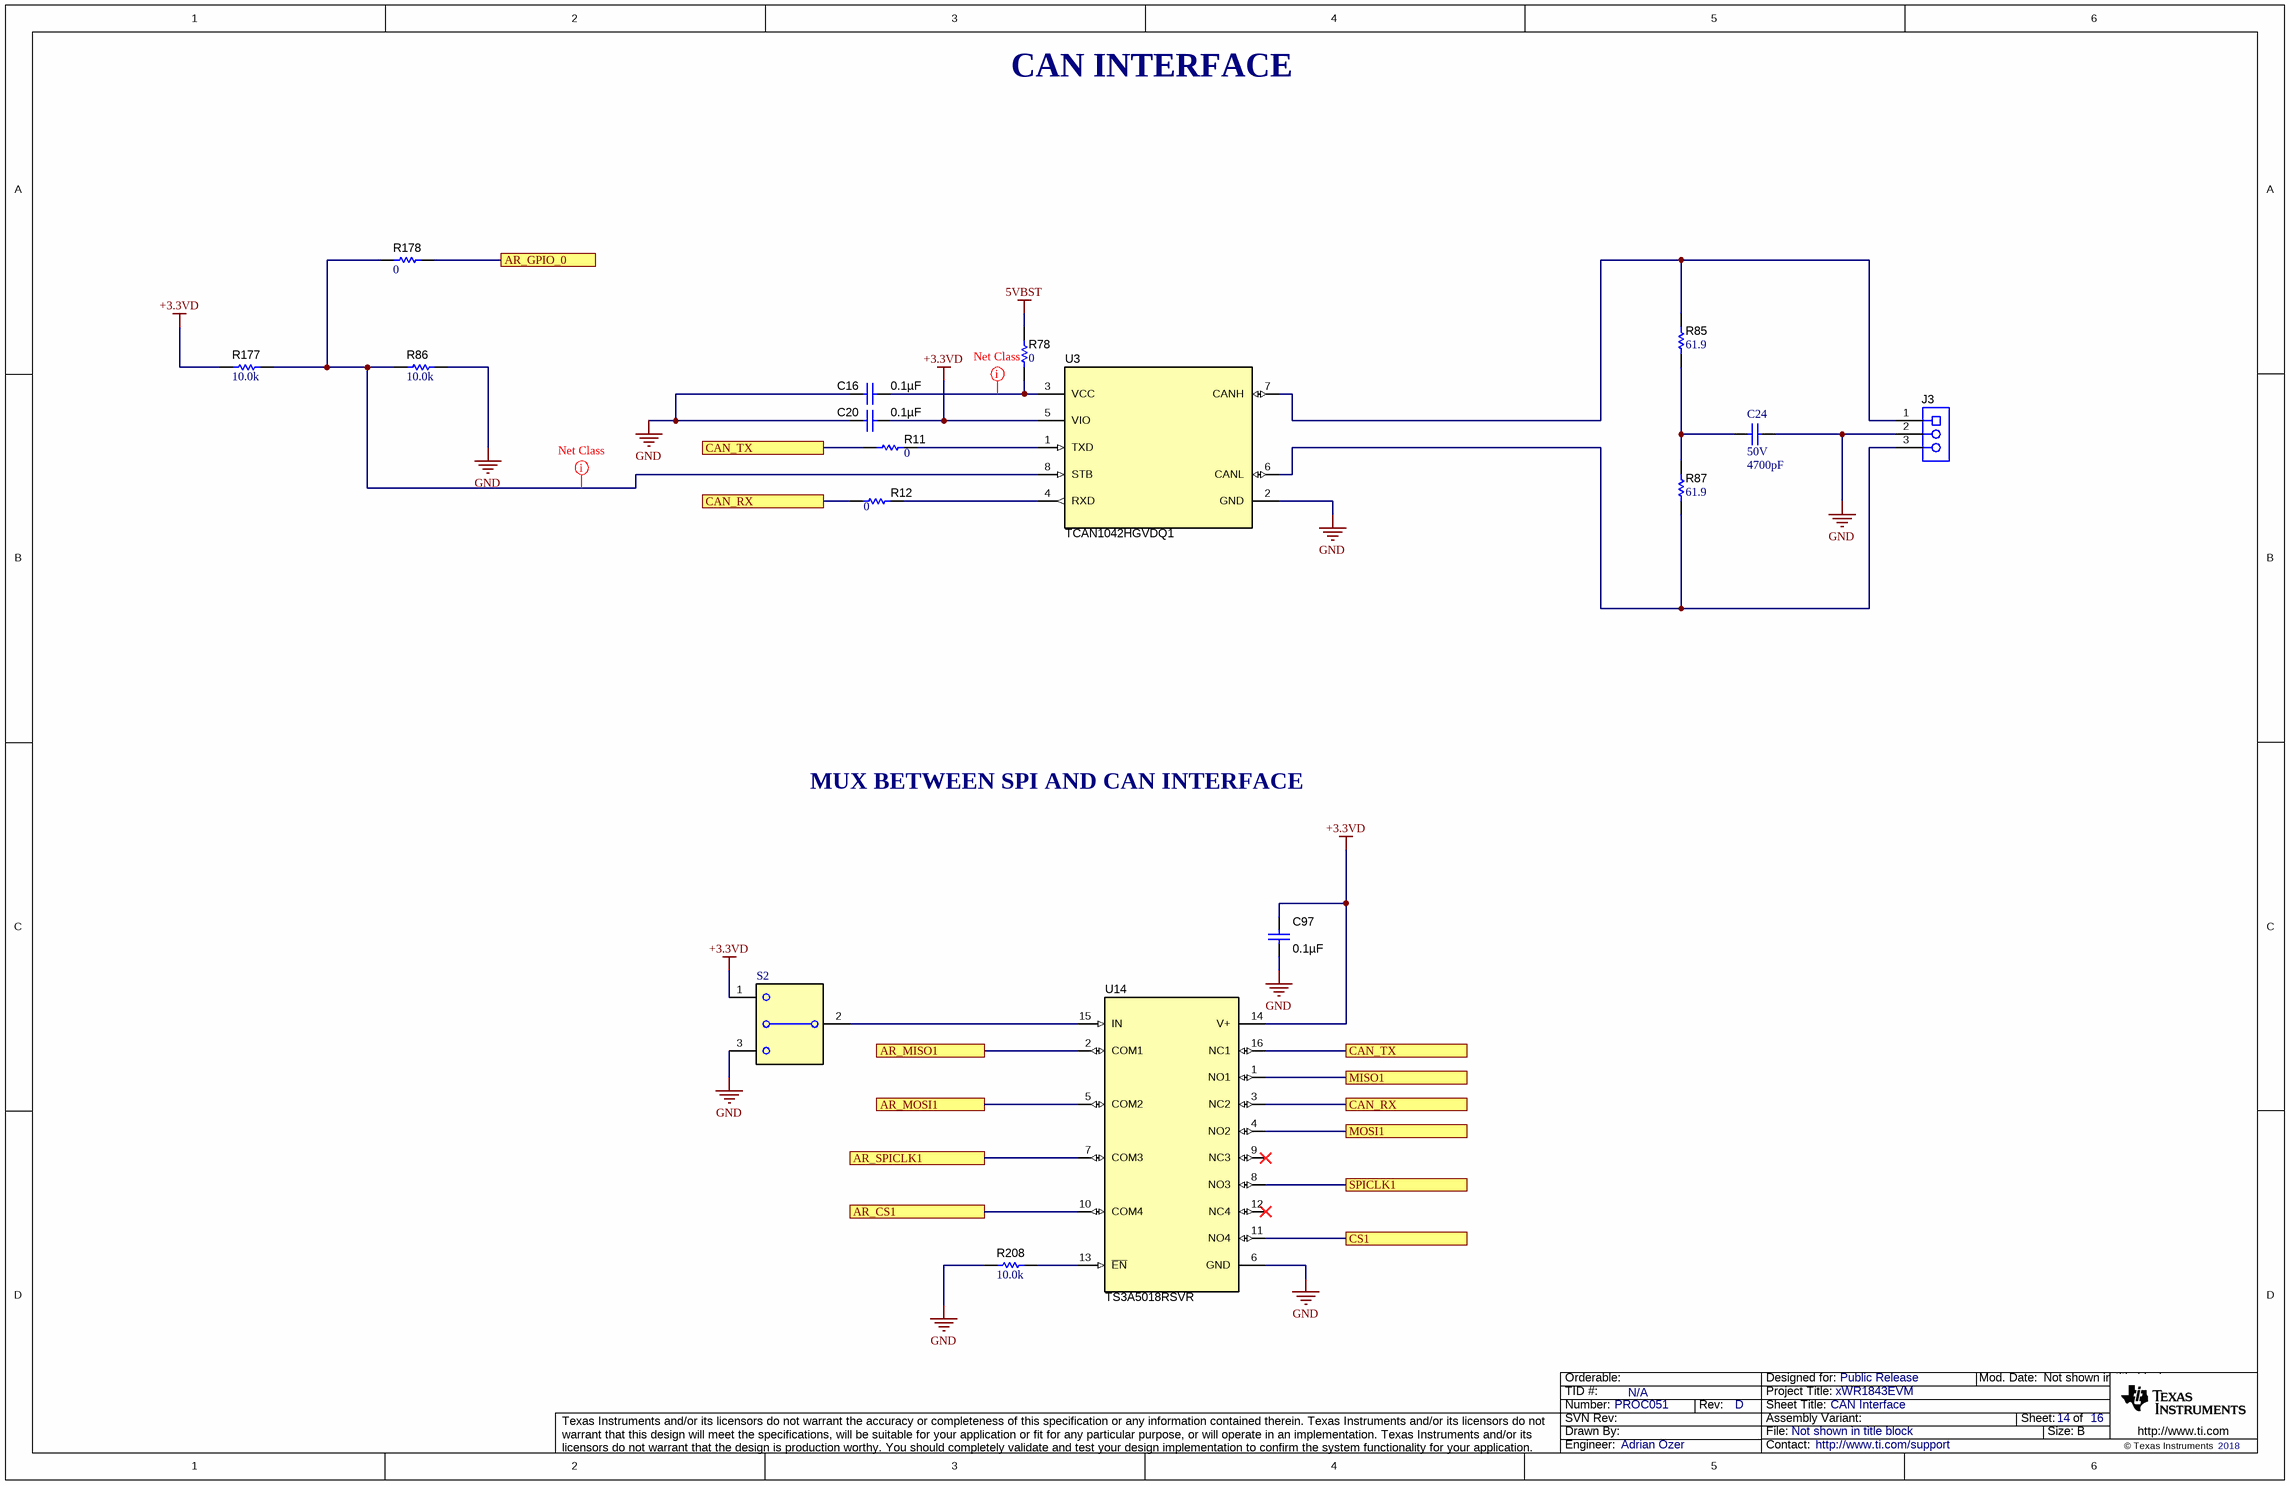
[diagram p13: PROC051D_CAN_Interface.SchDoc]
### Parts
C16  ValueDisplayed: 0.1µF  [0402L]  (hidden comment: C0402C104K8RACTU)
C20  ValueDisplayed: 0.1µF  [0402L]  (hidden comment: C0402C104K8RACTU)
C24  VDC_V: 50V  ValueDisplayed: 4700pF  [0402]  (hidden comment: GCM155R71H472KA37D)
C97  ValueDisplayed: 0.1µF  [0402L]  (hidden comment: C0402C104K8RACTU)
J3  OSTTE030161  [On-Shore_OSTTE030161]  (value not drawn)
R11  value 0  [0402L]  (hidden comment: ERJ-2GE0R00X)
R12  ValueDisplayed: 0  [0402L]  (hidden comment: ERJ-2GE0R00X)
R78  ValueDisplayed: 0  [0402L]  (hidden comment: ERJ-2GE0R00X)
R85  ValueDisplayed: 61.9  [0402L]  (hidden comment: CRCW040261R9FKED)
R86  ValueDisplayed: 10.0k  [0402L]  (hidden comment: CRCW040210K0FKED)
R87  ValueDisplayed: 61.9  [0402L]  (hidden comment: CRCW040261R9FKED)
R177  ValueDisplayed: 10.0k  [0402L]  (hidden comment: CRCW040210K0FKED)
R178  ValueDisplayed: 0  [0402L]  (hidden comment: ERJ-2GE0R00X)
R208  ValueDisplayed: 10.0k  [0402L]  (hidden comment: CRCW040210K0FKED)
S2  CJS-1201TA  [SW_CJS_1201A]  (value not drawn)
U3  TCAN1042HGVDQ1  [D0008A_L]
U14  TS3A5018RSVR  [RSV0016A]

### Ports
AR_CS1, AR_GPIO_0, AR_MISO1, AR_MOSI1, AR_SPICLK1, CAN_RX, CAN_TX, CS1, MISO1, MOSI1, SPICLK1

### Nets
5VBST: R78.2
+3.3VD: C20.2 C97.2 R177.1 S2.1 U3.5(VIO) U14.14(V+)
GND: C16.1 C20.1 C24.1 C97.1 J3.2 R86.2 R208.2 S2.3 U3.2(GND) U14.6(GND)
AR_CS1: U14.10(COM4) ; port AR_CS1
AR_GPIO_0: R178.2 ; port AR_GPIO_0
AR_MISO1: U14.2(COM1) ; port AR_MISO1
AR_MOSI1: U14.5(COM2) ; port AR_MOSI1
AR_SPICLK1: U14.7(COM3) ; port AR_SPICLK1
CAN_RX: R12.1 U14.3(NC2) ; port CAN_RX
CAN_TX: R11.1 U14.16(NC1) ; port CAN_TX
CS1: U14.11(NO4) ; port CS1
MISO1: U14.1(NO1) ; port MISO1
MOSI1: U14.4(NO2) ; port MOSI1
SPICLK1: U14.8(NO3) ; port SPICLK1
NetC16_2: C16.2 R78.1 U3.3(VCC)
NetC24_2: C24.2 R85.1 R87.2
NetJ3_1: J3.1 R85.2 U3.7(CANH)
NetJ3_3: J3.3 R87.1 U3.6(CANL)
NetR11_2: R11.2 U3.1(TXD)
NetR12_2: R12.2 U3.4(RXD)
NetR86_1: R86.1 R177.2 R178.1 U3.8(STB)
NetR208_1: R208.1 U14.13(~{EN})
NetS2_2: S2.2(COM) U14.15(IN)

Not connected (* = marked no-connect by the designer): U14 9(NC3)* 12(NC4)*

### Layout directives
net class PWR: NetC16_2, NetR86_1

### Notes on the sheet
- CAN INTERFACE
- MUX BETWEEN SPI AND CAN INTERFACE

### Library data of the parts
C16 C20 C97 = CMP-0078241-1: CAP, CERM, 0.1 µF, 10 V,+/- 10%, X7R, 0402; Manufacturer: Kemet; TaMin_C: -55°C; Polarized: N; SizeAreaWB_mm2: 3; U/M: EA; Value: 0.1uF; TaMax_C: 125°C; SizeZ_mm: 0.6; SizeX_mm: 1; SizeY_mm: 0.5; Cap_Case: 0402; Value2: 10V; Cap_F: 100nF; AEC Category: Q200
C24 = CMP-0006361-2: CAP, CERM, 4700 pF, 50 V, +/- 10%, X7R, AEC-Q200 Grade 1, 0402; Manufacturer: MuRata; TaMin_C: -55°C; Polarized: N; SizeAreaWB_mm2: 3; Value1: Unknown; U/M: EA; Value: 4700pF; TaMax_C: 125°C; SizeZ_mm: 0.6; SizeX_mm: 1; SizeY_mm: 0.5; AEC Qualified: Y; Cap_F: 4.7nF; AEC Category: Q200
J3 = CMP-0075352-1: Terminal Block, 3.5mm, 3x1, Tin, R/A, TH; Manufacturer: On-Shore Technology; CNHeader: False; Current_A: 10A; Green_Lifecycle: Not Set; Gender: Female; Cert_CSA: Y; Green_REACh: Incomplete; Voltage_V: 125V; Row_Count: 1; Pitch_mm: 3.5; CT: True
R11 = CMP-0026992-3: RES, 0, 5%, 0.1 W, AEC-Q200 Grade 0, 0402; Manufacturer: Panasonic; Power_W: 100mW; TempCo: 600 ppm/C; Value_Code: 0000; EIA_Code: E24; SizeX_mm: 1; SizeY_mm: 0.5; SizeZ_mm: 0.6; Value2: 0.1W; AEC Qualified: Y; VDC_V: 50V; AEC Category: Q200; SizeAreaWB_mm2: 3
R12 R78 R178 = CMP-0026992-3: RES, 0, 5%, 0.1 W, AEC-Q200 Grade 0, 0402; Manufacturer: Panasonic; Power_W: 100mW; TempCo: 600 ppm/C; Value_Code: 0000; Value: 0; EIA_Code: E24; SizeX_mm: 1; SizeY_mm: 0.5; SizeZ_mm: 0.6; Value2: 0.1W; AEC Qualified: Y; VDC_V: 50V; AEC Category: Q200; SizeAreaWB_mm2: 3
R85 R87 = CMP-0026491-2: RES, 61.9, 1%, 0.063 W, AEC-Q200 Grade 0, 0402; Manufacturer: Vishay-Dale; Power_W: 63mW; TempCo: 100 ppm/C; Value_Code: 61R9; Value: 61.9; EIA_Code: E96; SizeX_mm: 1; SizeY_mm: 0.5; SizeZ_mm: 0.6; Value2: 0.063W; AEC Qualified: Y; VDC_V: 50V; AEC Category: Q200; AEC Grade: 0
R86 R177 R208 = CMP-0025958-3: RES, 10.0 k, 1%, 0.063 W, AEC-Q200 Grade 0, 0402; Manufacturer: Vishay-Dale; Power_W: 63mW; TempCo: 100 ppm/C; Value_Code: 10k0; Value: 10.0k; EIA_Code: E96; Res_ohm: 10k; SizeX_mm: 1; SizeY_mm: 0.5; SizeZ_mm: 0.6; Value2: 0.063W; AEC Qualified: Y; VDC_V: 50V; AEC Category: Q200; AEC Grade: 0
S2 = CMP-0002159-2: Slide SW, SPDT 0.1A 50VDC; Manufacturer: Copal Electronics; CurrentRating_mA: 100A; SwitchFunction: On-Off-On; VDC_V: 50V; PositionCount: 1; CompType: Switch
U3 = CMP-0075992-1: Automotive Fault Protected CAN Transceiver With Flexible Data-Rate, D0008A (SOIC-8); Manufacturer: Texas Instruments; Alternate PartNumber: TCAN1042HGVDRQ1; SizeAreaWB_mm2: 56.58; SizeArea_mm2: 30.38; SizeZ_mm: 1.75; SizeY_mm: 6.2; U/M: EA; CompType: IC; SizeX_mm: 4.9
U14 = CMP-0067415-1: 10-Ohm Quad SPDT Analog Switch, RSV0016A (UQFN-16); Alternate Manufacturer: Texas Instruments; SizeAreaWB_mm2: 10.08; U/M: EA; SizeZ_mm: 0.55; SizeX_mm: 1.8; SizeY_mm: 2.6; SizeArea_mm2: 4.68; CompType: IC

## Sheet PROC051D_Tempsensor.SchDoc: Tempsensor
size 431 x 279 mm; Date: Not shown in title block; ApprovedBy: Not shown in title block; CheckedBy: Not shown in title block; Author: Not shown in title block; CompanyName: Not shown in title block; Engineer: Not shown in title block; Organization: Not shown in title block; Address1: Not shown in title block; Address2: Not shown in title block; Address3: Not shown in title block; Address4: Not shown in title block; DocumentNumber: 15; Revision: Use project parameter SCH_Rev; SheetNumber: 15; SheetTotal: 16; PageSetup: Record=PageOptions¦CenterHorizontal=True¦CenterVertical=True¦PrintScale=1.00¦XCorrection=1.00¦YCorrection=1.00¦PrintKind=0¦BorderSize=5000000¦LeftOffset=0¦BottomOffset=0¦Orientation=2¦PaperLength=1000¦PaperWidth=1000¦Scale=100¦PaperSource=15¦PrintQuality=600¦MediaType=1¦DitherType=10¦PaperKind=Letter¦PrintScaleMode=1

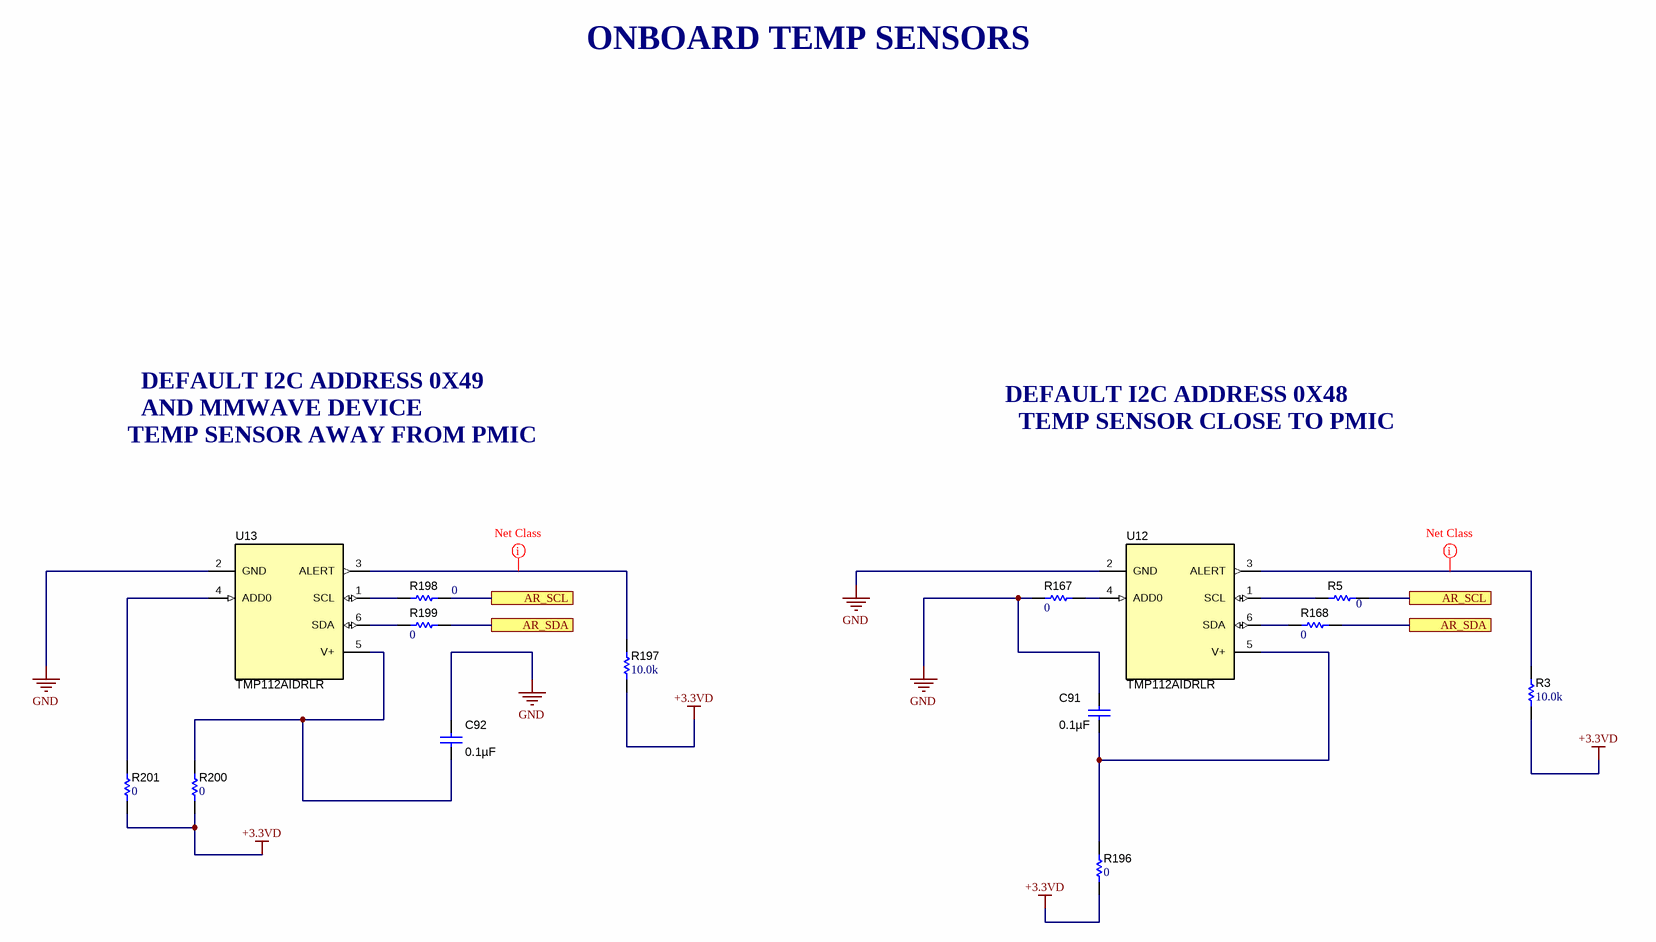
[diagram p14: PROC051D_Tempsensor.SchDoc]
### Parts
C91  ValueDisplayed: 0.1µF  [0402L]  (hidden comment: C0402C104K8RACTU)
C92  ValueDisplayed: 0.1µF  [0402L]  (hidden comment: C0402C104K8RACTU)
R3  ValueDisplayed: 10.0k  [0402L]  (hidden comment: CRCW040210K0FKED)
R5  ValueDisplayed: 0  [0201_Silk]  (hidden comment: CRCW02010000Z0ED)
R167  ValueDisplayed: 0  [0201_Silk]  (hidden comment: CRCW02010000Z0ED)
R168  ValueDisplayed: 0  [0201_Silk]  (hidden comment: CRCW02010000Z0ED)
R196  ValueDisplayed: 0  [0402L]  (hidden comment: ERJ-2GE0R00X)
R197  ValueDisplayed: 10.0k  [0402L]  (hidden comment: CRCW040210K0FKED)
R198  ValueDisplayed: 0  [0201_Silk]  (hidden comment: CRCW02010000Z0ED)
R199  ValueDisplayed: 0  [0201_Silk]  (hidden comment: CRCW02010000Z0ED)
R200  ValueDisplayed: 0  [0402L]  (hidden comment: ERJ-2GE0R00X)
R201  ValueDisplayed: 0  [0201_Silk]  (hidden comment: CRCW02010000Z0ED)
U12  TMP112AIDRLR  [DRL0006A]
U13  TMP112AIDRLR  [DRL0006A]

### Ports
AR_SCL, AR_SDA

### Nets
+3.3VD: R3.2 R196.2 R197.2 R200.2 R201.2
GND: C91.1 C92.1 R167.1 U12.2(GND) U13.2(GND)
AR_SCL: R5.1 R198.1 ; port AR_SCL
AR_SDA: R168.2 R199.2 ; port AR_SDA
NetC91_2: C91.2 R196.1 U12.5(V+)
NetC92_2: C92.2 R200.1 U13.5(V+)
NetR3_1: R3.1 U12.3(ALERT)
NetR5_2: R5.2 U12.1(SCL)
NetR167_2: R167.2 U12.4(ADD0)
NetR168_1: R168.1 U12.6(SDA)
NetR197_1: R197.1 U13.3(ALERT)
NetR198_2: R198.2 U13.1(SCL)
NetR199_1: R199.1 U13.6(SDA)
NetR201_1: R201.1 U13.4(ADD0)

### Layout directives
net class PWR: NetR3_1, NetR197_1

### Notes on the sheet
- ONBOARD TEMP SENSORS
- DEFAULT I2C ADDRESS 0X49
- DEFAULT I2C ADDRESS 0X48
- TEMP SENSOR AWAY FROM PMIC
- AND MMWAVE DEVICE
- TEMP SENSOR CLOSE TO PMIC

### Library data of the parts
C91 C92 = CMP-0078241-1: as C16 on sheet PROC051D_CAN_Interface
R3 R197 = CMP-0025958-3: as R86 on sheet PROC051D_CAN_Interface
R5 R167 R168 R198 R199 R201 = CMP-0027008-4: RES, 0, 5%, 0.05 W, 0201; Manufacturer: Vishay-Dale; Power_W: 50mW; TempCo: ppm/C; Value_Code: 0000; Value: 0; EIA_Code: E24; SizeX_mm: 0.6; SizeY_mm: 0.3; SizeZ_mm: 0.26; Value2: 0.05W; SizeArea_mm2: 0.18; AEC Qualified: N; AEC Category: Q200
R196 R200 = CMP-0026992-3: as R12 on sheet PROC051D_CAN_Interface
U12 U13 = CMP-0067397-2: 1.4V-Capable +/-0.5degC Temperature Sensor with Alert Function and I2C/SMBus interface in SOT-563, DRL0006A (SOT-OTHER-6); Alternate PartNumber: TMP112AIDRLT; Alternate Manufacturer: Texas Instruments; Green_Lifecycle: Active; SizeAreaWB_mm2: 6.76; Green_REACh: Passed; U/M: EA; SizeZ_mm: 0.6; SizeX_mm: 1.6; SizeArea_mm2: 2.56; CompType: IC

## Sheet PROC051D_Hardware.SchDoc: Hardware
size 431 x 279 mm; Date: Not shown in title block; ApprovedBy: Not shown in title block; CheckedBy: Not shown in title block; Author: Not shown in title block; CompanyName: Not shown in title block; Engineer: Not shown in title block; Organization: Not shown in title block; Address1: Not shown in title block; Address2: Not shown in title block; Address3: Not shown in title block; Address4: Not shown in title block; DocumentNumber: 16; Revision: Use project parameter SCH_Rev; SheetNumber: 16; SheetTotal: 16; PageSetup: Record=PageOptions¦CenterHorizontal=True¦CenterVertical=True¦PrintScale=1.00¦XCorrection=1.00¦YCorrection=1.00¦PrintKind=0¦BorderSize=5000000¦LeftOffset=0¦BottomOffset=0¦Orientation=2¦PaperLength=1000¦PaperWidth=1000¦Scale=100¦PaperSource=15¦PrintQuality=600¦MediaType=1¦DitherType=10¦PaperKind=Letter¦PrintScaleMode=1

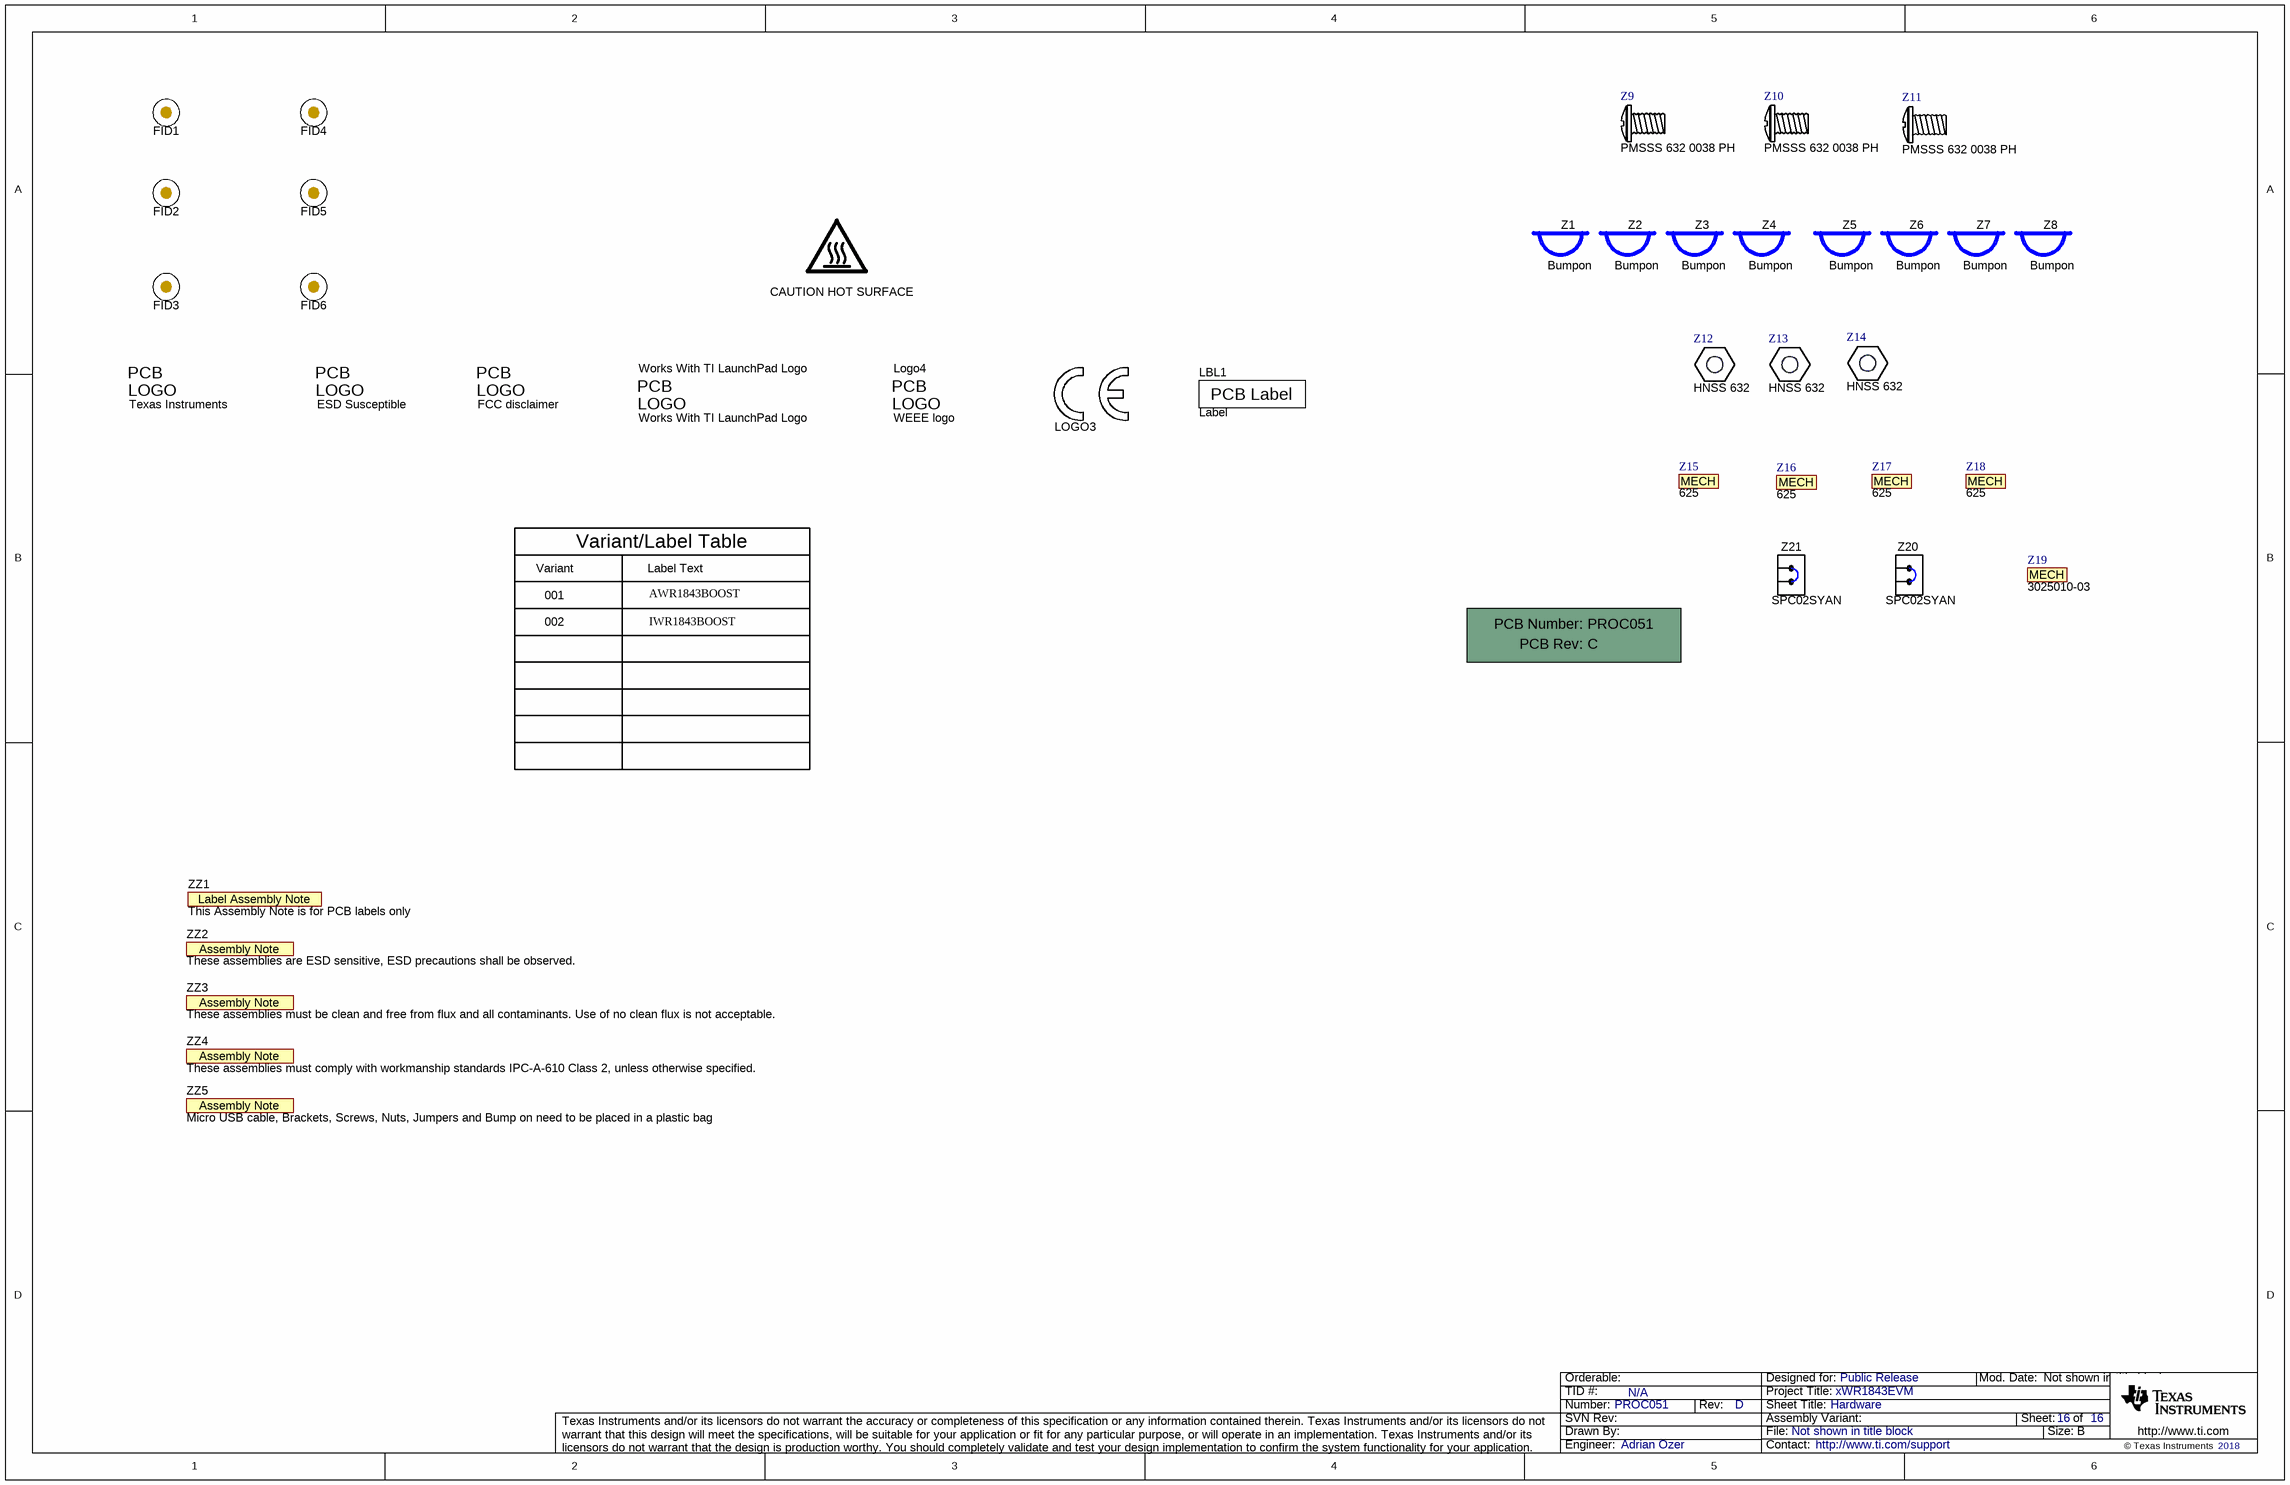
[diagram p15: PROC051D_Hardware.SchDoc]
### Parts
!PCB  PROC051  (value not drawn)  (mechanical)
CAUTION_HOT_SURFACE  CAUTION HOT SURFACE  [IEC_HotSurface_Small]  (no BOM)
ESD_Susceptible  ESD Susceptible  [ESD_Overlay_Small]  (no BOM)
FID1  Fiducial  [Fiducial10-20]  (value not drawn)
FID2  Fiducial  [Fiducial10-20]  (value not drawn)
FID3  Fiducial  [Fiducial10-20]  (value not drawn)
FID4  Fiducial  [Fiducial10-20]  (value not drawn)
FID5  Fiducial  [Fiducial10-20]  (value not drawn)
FID6  Fiducial  [Fiducial10-20]  (value not drawn)
LBL1  Label  [Label_650x200]
Logo1  Texas Instruments  [TI_Stacked_Overlay_Small]  (no BOM)
Logo2  FCC disclaimer  [FCC_disclaimer]  (no BOM)
LOGO3  CE Mark  [CE_Mark_5mm]  (value not drawn)  (no BOM)
Logo4  WEEE logo  [WEEE_Minimum]  (no BOM)
Works_With_TI_LaunchPad_Logo  Works With TI LaunchPad Logo  [WorksWithTILaunchPad]  (graphical)
Z1  Bumpon  [Bumpon_SJ61A1]  (mechanical)
Z2  Bumpon  [Bumpon_SJ61A1]  (mechanical)
Z3  Bumpon  [Bumpon_SJ61A1]  (mechanical)
Z4  Bumpon  [Bumpon_SJ61A1]  (mechanical)
Z5  Bumpon  [Bumpon_SJ61A1]  (mechanical)
Z6  Bumpon  [Bumpon_SJ61A1]  (mechanical)
Z7  Bumpon  [Bumpon_SJ61A1]  (mechanical)
Z8  Bumpon  [Bumpon_SJ61A1]  (mechanical)
Z9  PMSSS 632 0038 PH  [B-F_PMSSS_632_0038_PH]  (mechanical)
Z10  PMSSS 632 0038 PH  [B-F_PMSSS_632_0038_PH]  (mechanical)
Z11  PMSSS 632 0038 PH  [B-F_PMSSS_632_0038_PH]  (mechanical)
Z12  HNSS 632  [B-F_HNSS-632]  (mechanical)
Z13  HNSS 632  [B-F_HNSS-632]  (mechanical)
Z14  HNSS 632  [B-F_HNSS-632]  (mechanical)
Z15  625  (mechanical)
Z16  625  (mechanical)
Z17  625  (mechanical)
Z18  625  (mechanical)
Z19  3025010-03  (mechanical)
Z20  SPC02SYAN  [SPC02SYAN]  (mechanical)
Z21  SPC02SYAN  [SPC02SYAN]  (mechanical)
ZZ1  This Assembly Note is for PCB labels only  [AssemblyNoteLabel]  (no BOM)
ZZ2  These assemblies are ESD sensitive, ESD precautions shall be observed.  [AssemblyNote]  (no BOM)
ZZ3  These assemblies must be clean and free from flux and all contaminants. Use of no clean flux is not acceptable.  [AssemblyNote]  (no BOM)
ZZ4  These assemblies must comply with workmanship standards IPC-A-610 Class 2, unless otherwise specified.  [AssemblyNote]  (no BOM)
ZZ5  Micro USB cable, Brackets, Screws, Nuts, Jumpers and Bump on need to be placed in a plastic bag  [AssemblyNote]  (no BOM)

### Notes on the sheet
- Variant
- Variant/Label Table
- Label Text
- 001
- 002
- AWR1843BOOST
- IWR1843BOOST

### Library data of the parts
!PCB = CMP-0003618-2: Printed Circuit Board; Manufacturer: Any; CompType: PCB
CAUTION_HOT_SURFACE = CMP-0074837-1: IEC 61010-1 Hot Surface Warning; Library Reference: IEC_HotSurface; SymbolCreator: a0412235
ESD_Susceptible = CMP-0074840-1: ESD Susceptible Symbol; Library Reference: Logo; SymbolCreator: a0412235; Lib Reference: ESD_Susceptible
FID1-FID6 = CMP-0077181-1: Fiducial mark.  There is nothing to buy or mount.
LBL1 = CMP-0003625-1: Thermal Transfer Printable Labels, 0.650" W x 0.200" H - 10,000 per roll; Manufacturer: Brady; PartNumber: THT-14-423-10; Note: Size: 0.65" x 0.20 "
Logo1 = CMP-0074838-1: Texas Instrument Corporate Signature; SymbolCreator: a0412235; Lib Reference: TI_Logo; Library Reference: Logo
Logo2 = CMP-0074847-1: FCC_disclaimer; Library Reference: Logo
LOGO3 = CMP-0074844-1: SymbolCreator: a0412235
Logo4 = CMP-0074769-1
Works_With_TI_LaunchPad_Logo = CMP-0077108-1
Z1-Z8 = CMP-0003621-1: Bumpon, Cylindrical, 0.312 X 0.200, Black; Manufacturer: 3M; PartNumber: SJ61A1
Z9-Z11 = CMP-0003820-1: MACHINE SCREW PAN PHILLIPS 6-32; Manufacturer: B&F Fastener Supply; Note: Symbol and footprint updated; CompType: Hardware
Z12-Z14 = CMP-0067637-3: Nut, Hex, 5/16", Stainless Steel, 6-32; Manufacturer: B&F Fastener Supply
Z15-Z18 = CMP-0085300-1: Aluminum Mounting Bracket; Manufacturer: Keystone
Z19 = CMP-0085299-1: Cable, USB A Male to Micro B Male 3'; Manufacturer: Qualtek Electronics Corporation
Z20 Z21 = CMP-0003642-1: Shunt, 100mil, Flash Gold, Black; Manufacturer: Sullins Connector Solutions; Value: 1x2; Note: You can "mate" this to a header by matching the designator.  i.e. use SH-J3 for header J3
ZZ1 = CMP-0003616-3
ZZ2 = CMP-0077236-1
ZZ3 = CMP-0077237-1
ZZ4 = CMP-0077238-1
ZZ5 = AssemblyNote: SymbolCreator: codlsc

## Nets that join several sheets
1V8: PROC051D_PWR_In_Reference (C38.1 L2.2 R119.1), PROC051D_LC_Filtering_Reference (L6.1)
1V24: PROC051D_PWR_In_Reference (11 pins), PROC051D_LC_Filtering_Reference (L5.1)
3V3: PROC051D_PWR_In_Reference (9 pins), PROC051D_RST_LEDs (R133.1)
3V3_REF: PROC051D_PWR_In_Reference (20 pins), PROC051D_LC_Filtering_Reference (L10.1), PROC051D_QSPI_Flash_Reference (R37.1 R38.2 R41.2 R43.2), PROC051D_SOP_Headers_Reference (S1.4 S1.5 S1.6)
5VBST: PROC051D_PWR_In_Reference (C82.1 C93.1 U4.8), PROC051D_CAN_Interface (R78.2)
+3.3VD: PROC051D_DUT_Reference (6 pins), PROC051D_RST_LEDs (8 pins), PROC051D_VPP_Supply (C86.2 R194.1 U11.1 U11.2), PROC051D_LP Connector (R172.2 R173.2), PROC051D_XDS110 Interface_1A (6 pins), PROC051D_XDS110 Interface_1B (20 pins), PROC051D_CAN_Interface (6 pins), PROC051D_Tempsensor (5 pins)
AR_1P0_RF1: PROC051D_DUT_Reference (R46.2 U2.G5 U2.H5 U2.J5), PROC051D_Decoupling_Caps_Reference (C45.2 C47.2), PROC051D_LC_Filtering_Reference (C19.1 C98.1 C100.1 L8.2)
AR_1P0_RF2: PROC051D_DUT_Reference (R100.2 U2.C2 U2.D2), PROC051D_Decoupling_Caps_Reference (C57.2 C58.2), PROC051D_LC_Filtering_Reference (5 pins)
AR_1V4_APLL: PROC051D_DUT_Reference (U2.A10), PROC051D_Decoupling_Caps_Reference (C13.2)
AR_1V4_SYNTH: PROC051D_DUT_Reference (U2.B13), PROC051D_Decoupling_Caps_Reference (C14.2)
AR_1V8: PROC051D_DUT_Reference (6 pins), PROC051D_Decoupling_Caps_Reference (8 pins), PROC051D_PWR_In_Reference (R150.2), PROC051D_LC_Filtering_Reference (C99.1 C104.1 L6.2)
AR_1V24: PROC051D_DUT_Reference (6 pins), PROC051D_Decoupling_Caps_Reference (6 pins), PROC051D_PWR_In_Reference (R146.2), PROC051D_LC_Filtering_Reference (C55.1 C105.1 L5.2)
AR_3V3: PROC051D_DUT_Reference (U2.F15 U2.R10), PROC051D_Decoupling_Caps_Reference (C5.2 C84.2 C87.2), PROC051D_LC_Filtering_Reference (C80.1 L10.2)
AR_VBGAP: PROC051D_DUT_Reference (U2.B10), PROC051D_Decoupling_Caps_Reference (C56.1)
AR_VOUT_PA: PROC051D_DUT_Reference (U2.A2 U2.B2), PROC051D_Decoupling_Caps_Reference (C10.2 C65.2 C83.2), PROC051D_LC_Filtering_Reference (R137.2)
GND: PROC051D_DUT_Reference (76 pins), PROC051D_Decoupling_Caps_Reference (27 pins), PROC051D_PWR_In_Reference (75 pins), PROC051D_LC_Filtering_Reference (11 pins), PROC051D_QSPI_Flash_Reference (C1.1 C2.1 U1.4 U1.9), PROC051D_SOP_Headers_Reference (R88.1 R96.1 R114.1), PROC051D_RST_LEDs (8 pins), PROC051D_VPP_Supply (5 pins), PROC051D_HD Connector (14 pins), PROC051D_LP Connector (J5.2 J6.4 P1.2), PROC051D_XDS110 Interface_1A (15 pins), PROC051D_XDS110 Interface_1B (21 pins), PROC051D_CAN_Interface (10 pins), PROC051D_Tempsensor (5 pins)
MCU_3V3: PROC051D_RST_LEDs (R130.1), PROC051D_LP Connector (J6.1)
VCC_LDO_OUT: PROC051D_PWR_In_Reference (9 pins), PROC051D_LC_Filtering_Reference (L8.1 L9.1)
VDDC_1: PROC051D_XDS110 Interface_1A (C62.1 C64.2 C74.2 C75.2), PROC051D_XDS110 Interface_1B (U6.87 U6.115)
VIN: PROC051D_PWR_In_Reference (11 pins), PROC051D_HD Connector (R34.2), PROC051D_LP Connector (R115.2)
VPP_1P7: PROC051D_DUT_Reference (C8.1 U2.L13), PROC051D_VPP_Supply (P7.1)
XDSET_1_VBUS: PROC051D_XDS110 Interface_1A (R151.2 R161.2 U10.6), PROC051D_XDS110 Interface_1B (R154.2)
AR_ANAMUX: PROC051D_DUT_Reference (U2.C13), PROC051D_LP Connector (P1.3)
AR_ANATEST1: PROC051D_DUT_Reference (R46.1 U2.P1), PROC051D_LP Connector (R104.2)
AR_ANATEST2: PROC051D_DUT_Reference (R100.1 U2.P2), PROC051D_LP Connector (R94.2)
AR_ANATEST3: PROC051D_DUT_Reference (U2.P3), PROC051D_LP Connector (R105.2)
AR_ANATEST4: PROC051D_DUT_Reference (U2.R2), PROC051D_LP Connector (R106.2)
AR_BSS_LOGGER: PROC051D_DUT_Reference (U2.H14), PROC051D_LP Connector (R31.1), PROC051D_XDS110 Interface_1B (R135.1)
AR_CS1: PROC051D_DUT_Reference (R14.1 U2.E15), PROC051D_CAN_Interface (U14.10)
AR_DMM_CLK: PROC051D_DUT_Reference (U2.N15), PROC051D_HD Connector (R54.1)
AR_DMM_SYNC: PROC051D_DUT_Reference (U2.N14), PROC051D_HD Connector (R55.1)
AR_DP0: PROC051D_DUT_Reference (U2.R4), PROC051D_HD Connector (R56.1)
AR_DP1: PROC051D_DUT_Reference (U2.P5), PROC051D_HD Connector (R57.1)
AR_DP2: PROC051D_DUT_Reference (U2.R5), PROC051D_HD Connector (R179.1)
AR_DP3: PROC051D_DUT_Reference (U2.P6), PROC051D_HD Connector (R180.1)
AR_DP4: PROC051D_DUT_Reference (U2.R7), PROC051D_HD Connector (R181.1)
AR_DP5: PROC051D_DUT_Reference (U2.P7), PROC051D_HD Connector (R182.1)
AR_DP6: PROC051D_DUT_Reference (U2.R8), PROC051D_HD Connector (R183.1)
AR_DP7: PROC051D_DUT_Reference (U2.P8), PROC051D_HD Connector (R184.1), PROC051D_LP Connector (R60.2)
AR_GPIO_0: PROC051D_DUT_Reference (U2.H13), PROC051D_LP Connector (R164.1), PROC051D_CAN_Interface (R178.2)
AR_GPIO_1: PROC051D_DUT_Reference (U2.J13), PROC051D_RST_LEDs (R72.2), PROC051D_LP Connector (R9.2)
AR_GPIO_2: PROC051D_DUT_Reference (U2.K13), PROC051D_PWR_In_Reference (R147.1), PROC051D_RST_LEDs (R110.2 R116.1), PROC051D_LP Connector (R8.2)
AR_HOSTINTR1: PROC051D_DUT_Reference (R13.2 U2.P13), PROC051D_HD Connector (R64.2), PROC051D_LP Connector (R10.2)
AR_LVDS_0_N: PROC051D_DUT_Reference (U2.J15), PROC051D_HD Connector (R48.2)
AR_LVDS_0_P: PROC051D_DUT_Reference (U2.J14), PROC051D_HD Connector (R49.2)
AR_LVDS_1_N: PROC051D_DUT_Reference (U2.K15), PROC051D_HD Connector (R50.2)
AR_LVDS_1_P: PROC051D_DUT_Reference (U2.K14), PROC051D_HD Connector (R51.2)
AR_LVDS_CLK_N: PROC051D_DUT_Reference (U2.L15), PROC051D_HD Connector (R52.2)
AR_LVDS_CLK_P: PROC051D_DUT_Reference (U2.L14), PROC051D_HD Connector (R53.2)
AR_LVDS_FRCLK_N: PROC051D_DUT_Reference (U2.M15), PROC051D_HD Connector (R58.2)
AR_LVDS_FRCLK_P: PROC051D_DUT_Reference (U2.M14), PROC051D_HD Connector (R59.2)
AR_MCUCLKOUT: PROC051D_DUT_Reference (U2.N8), PROC051D_PWR_In_Reference (R148.2), PROC051D_LP Connector (R25.1)
AR_MISO1: PROC051D_DUT_Reference (U2.E14), PROC051D_CAN_Interface (U14.2)
AR_MOSI1: PROC051D_DUT_Reference (U2.D13), PROC051D_CAN_Interface (U14.5)
AR_MSS_LOGGER: PROC051D_DUT_Reference (U2.F14), PROC051D_LP Connector (R26.1), PROC051D_XDS110 Interface_1B (R136.1)
AR_NERR_OUT: PROC051D_DUT_Reference (R91.1 U2.N6), PROC051D_RST_LEDs (DS1.2), PROC051D_HD Connector (R63.2), PROC051D_LP Connector (R19.1)
AR_NERRIN: PROC051D_DUT_Reference (R16.1 U2.N7), PROC051D_LP Connector (R24.1)
AR_NRST: PROC051D_DUT_Reference (U2.R3), PROC051D_PWR_In_Reference (C94.2 R143.1 R144.1 R159.1), PROC051D_RST_LEDs (6 pins)
AR_NRST_MCU: PROC051D_RST_LEDs (R77.1), PROC051D_HD Connector (R20.1), PROC051D_LP Connector (R2.2)
AR_NRST_XDS: PROC051D_RST_LEDs (R80.1), PROC051D_XDS110 Interface_1B (U6.40)
AR_OSC_CLKOUT: PROC051D_DUT_Reference (U2.A14), PROC051D_HD Connector (R111.1)
AR_PMIC_CLKOUT_SOP2: PROC051D_DUT_Reference (U2.P9), PROC051D_SOP_Headers_Reference (R97.1 R98.1), PROC051D_LP Connector (R109.2)
AR_QSPI_CS: PROC051D_DUT_Reference (U2.P11), PROC051D_QSPI_Flash_Reference (R38.1 U1.1)
AR_QSPI_D0: PROC051D_DUT_Reference (U2.R13), PROC051D_QSPI_Flash_Reference (R45.2)
AR_QSPI_D1: PROC051D_DUT_Reference (U2.N12), PROC051D_QSPI_Flash_Reference (R39.1)
AR_QSPI_D2: PROC051D_DUT_Reference (U2.R14), PROC051D_QSPI_Flash_Reference (R42.1 R43.1)
AR_QSPI_D3: PROC051D_DUT_Reference (U2.P12), PROC051D_QSPI_Flash_Reference (R40.2 R41.1)
AR_QSPI_SCLK: PROC051D_DUT_Reference (U2.R12), PROC051D_QSPI_Flash_Reference (R44.2)
AR_RS232RX: PROC051D_DUT_Reference (U2.N4), PROC051D_HD Connector (R33.1), PROC051D_LP Connector (R166.1 R172.1), PROC051D_XDS110 Interface_1B (R129.1)
AR_RS232TX: PROC051D_DUT_Reference (U2.N5), PROC051D_HD Connector (R21.1), PROC051D_LP Connector (R169.1 R173.1), PROC051D_XDS110 Interface_1B (R128.1)
AR_SCL: PROC051D_DUT_Reference (R47.2 R171.1), PROC051D_PWR_In_Reference (R132.1 U4.20), PROC051D_HD Connector (R22.1), PROC051D_LP Connector (R163.1), PROC051D_Tempsensor (R5.1 R198.1)
AR_SDA: PROC051D_DUT_Reference (R81.2 R170.1), PROC051D_PWR_In_Reference (R131.1 U4.21), PROC051D_HD Connector (R23.1), PROC051D_LP Connector (R162.1), PROC051D_Tempsensor (R168.2 R199.2)
AR_SPICLK1: PROC051D_DUT_Reference (U2.E13), PROC051D_CAN_Interface (U14.7)
AR_SYNC_IN: PROC051D_DUT_Reference (U2.P4), PROC051D_HD Connector (R62.2), PROC051D_LP Connector (R165.1)
AR_SYNC_OUT_SOP1: PROC051D_DUT_Reference (U2.G13), PROC051D_SOP_Headers_Reference (R113.1), PROC051D_LP Connector (R108.2)
AR_TCK: PROC051D_DUT_Reference (U2.P10), PROC051D_HD Connector (R66.2 R70.1)
AR_TDI: PROC051D_DUT_Reference (U2.R11), PROC051D_HD Connector (R29.1 R30.1)
AR_TDO_SOP0: PROC051D_DUT_Reference (U2.N13), PROC051D_SOP_Headers_Reference (R89.1), PROC051D_HD Connector (R67.2 R71.1)
AR_TMS: PROC051D_DUT_Reference (U2.N10), PROC051D_HD Connector (R65.2 R69.1)
AR_VSENSE: PROC051D_DUT_Reference (U2.D14), PROC051D_LP Connector (P1.1)
AR_WARMRST: PROC051D_DUT_Reference (R15.1 U2.N9), PROC051D_PWR_In_Reference (R149.2), PROC051D_RST_LEDs (DS2.2), PROC051D_LP Connector (R18.1)
CS1: PROC051D_HD Connector (R17.1), PROC051D_LP Connector (R1.2), PROC051D_CAN_Interface (U14.11)
MCU_SOP0: PROC051D_SOP_Headers_Reference (R93.2), PROC051D_LP Connector (R36.1)
MCU_SOP1: PROC051D_SOP_Headers_Reference (R112.2), PROC051D_LP Connector (R35.1)
MCU_SOP2: PROC051D_SOP_Headers_Reference (R101.2), PROC051D_LP Connector (R32.1)
MISO1: PROC051D_HD Connector (R7.2), PROC051D_LP Connector (R6.2), PROC051D_CAN_Interface (U14.1)
MOSI1: PROC051D_HD Connector (R28.1), PROC051D_LP Connector (R4.2), PROC051D_CAN_Interface (U14.4)
PGOOD: PROC051D_PWR_In_Reference (R138.2 R141.2), PROC051D_HD Connector (R27.1), PROC051D_LP Connector (R107.2)
PMIC_CLK: PROC051D_PWR_In_Reference (R188.2), PROC051D_SOP_Headers_Reference (R97.2)
PMIC_EN1: PROC051D_PWR_In_Reference (R84.1 U4.11 U4.19 U8.19), PROC051D_LP Connector (R102.2)
SPICLK1: PROC051D_HD Connector (R75.1), PROC051D_LP Connector (R76.1), PROC051D_CAN_Interface (U14.8)
VBUS_1_DETECT: PROC051D_XDS110 Interface_1A (C69.2 R151.1 R153.2), PROC051D_XDS110 Interface_1B (U6.1)
XDSET_1_D_N: PROC051D_XDS110 Interface_1A (J8.2 U10.5), PROC051D_XDS110 Interface_1B (U6.93)
XDSET_1_D_P: PROC051D_XDS110 Interface_1A (J8.3 U10.4), PROC051D_XDS110 Interface_1B (U6.94)
XDSET_1_ID: PROC051D_XDS110 Interface_1A (J8.4 U10.2), PROC051D_XDS110 Interface_1B (R152.2)
XDSET_TCK: PROC051D_HD Connector (R70.2), PROC051D_XDS110 Interface_1B (U6.35)
XDSET_TDI: PROC051D_HD Connector (R30.2), PROC051D_XDS110 Interface_1B (U6.38)
XDSET_TDO: PROC051D_HD Connector (R71.2), PROC051D_XDS110 Interface_1B (U6.37)
XDSET_TMS: PROC051D_HD Connector (R69.2), PROC051D_XDS110 Interface_1B (U6.36)

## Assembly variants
001: not fitted C83 FID1 FID2 FID3 FID4 FID5 FID6 P1 P7 R8 R9 R21 R26 R33 R46 R83 R97 R100 R102 R108 R109 R115 R135 R147 R159 R164 R166 R169 R177 R178 R188 R190
002: not fitted C83 FID1 FID2 FID3 FID4 FID5 FID6 P1 P7 R8 R9 R21 R26 R33 R46 R83 R97 R100 R102 R108 R109 R115 R135 R147 R159 R164 R166 R169 R177 R178 R188 R190; alternate parts U2 -> CMP-0081106-1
